VERSION 5.7 ;
  NOWIREEXTENSIONATPIN ON ;
  DIVIDERCHAR "/" ;
  BUSBITCHARS "[]" ;
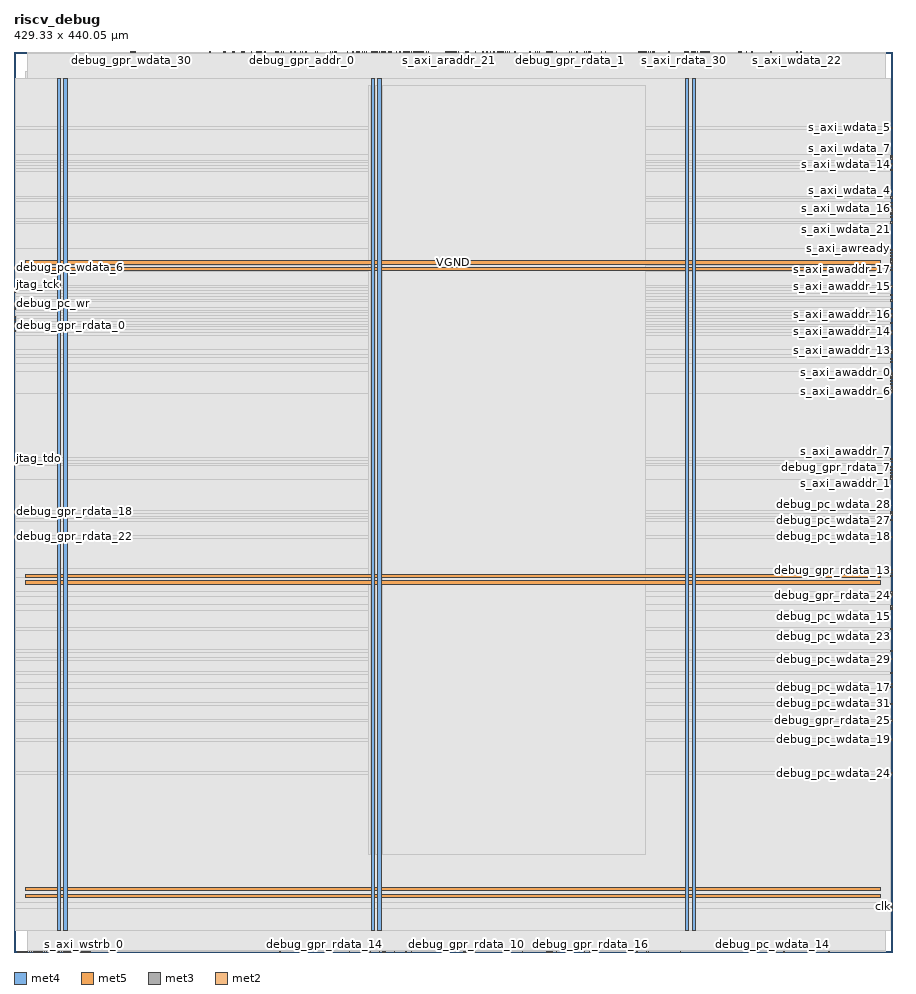
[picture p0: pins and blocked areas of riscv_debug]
MACRO riscv_debug
  CLASS BLOCK ;
  FOREIGN riscv_debug ;
  ORIGIN 0.000 0.000 ;
  SIZE 429.330 BY 440.050 ;
  PIN VGND
    DIRECTION INOUT ;
    USE GROUND ;
    PORT
      LAYER met4 ;
        RECT 24.340 10.640 25.940 427.280 ;
    END
    PORT
      LAYER met4 ;
        RECT 177.940 10.640 179.540 427.280 ;
    END
    PORT
      LAYER met4 ;
        RECT 331.540 10.640 333.140 427.280 ;
    END
    PORT
      LAYER met5 ;
        RECT 5.520 30.030 423.660 31.630 ;
    END
    PORT
      LAYER met5 ;
        RECT 5.520 183.210 423.660 184.810 ;
    END
    PORT
      LAYER met5 ;
        RECT 5.520 336.390 423.660 337.990 ;
    END
  END VGND
  PIN VPWR
    DIRECTION INOUT ;
    USE POWER ;
    PORT
      LAYER met4 ;
        RECT 21.040 10.640 22.640 427.280 ;
    END
    PORT
      LAYER met4 ;
        RECT 174.640 10.640 176.240 427.280 ;
    END
    PORT
      LAYER met4 ;
        RECT 328.240 10.640 329.840 427.280 ;
    END
    PORT
      LAYER met5 ;
        RECT 5.520 26.730 423.660 28.330 ;
    END
    PORT
      LAYER met5 ;
        RECT 5.520 179.910 423.660 181.510 ;
    END
    PORT
      LAYER met5 ;
        RECT 5.520 333.090 423.660 334.690 ;
    END
  END VPWR
  PIN clk
    DIRECTION INPUT ;
    USE SIGNAL ;
    ANTENNAGATEAREA 1.286700 ;
    ANTENNADIFFAREA 0.434700 ;
    PORT
      LAYER met3 ;
        RECT 428.730 21.800 429.330 22.400 ;
    END
  END clk
  PIN debug_gpr_addr_0
    DIRECTION OUTPUT ;
    USE SIGNAL ;
    ANTENNAGATEAREA 0.434700 ;
    ANTENNADIFFAREA 1.137600 ;
    PORT
      LAYER met2 ;
        RECT 140.850 439.770 141.130 440.050 ;
    END
  END debug_gpr_addr_0
  PIN debug_gpr_addr_1
    DIRECTION OUTPUT ;
    USE SIGNAL ;
    ANTENNAGATEAREA 0.434700 ;
    ANTENNADIFFAREA 1.137600 ;
    PORT
      LAYER met2 ;
        RECT 184.090 439.770 184.370 440.050 ;
    END
  END debug_gpr_addr_1
  PIN debug_gpr_addr_2
    DIRECTION OUTPUT ;
    USE SIGNAL ;
    ANTENNAGATEAREA 0.434700 ;
    ANTENNADIFFAREA 1.137600 ;
    PORT
      LAYER met2 ;
        RECT 176.730 439.770 177.010 440.050 ;
    END
  END debug_gpr_addr_2
  PIN debug_gpr_addr_3
    DIRECTION OUTPUT ;
    USE SIGNAL ;
    ANTENNAGATEAREA 0.434700 ;
    ANTENNADIFFAREA 1.137600 ;
    PORT
      LAYER met2 ;
        RECT 181.330 439.770 181.610 440.050 ;
    END
  END debug_gpr_addr_3
  PIN debug_gpr_addr_4
    DIRECTION OUTPUT ;
    USE SIGNAL ;
    ANTENNAGATEAREA 0.434700 ;
    ANTENNADIFFAREA 1.137600 ;
    PORT
      LAYER met2 ;
        RECT 177.650 439.770 177.930 440.050 ;
    END
  END debug_gpr_addr_4
  PIN debug_gpr_rdata_0
    DIRECTION INPUT ;
    USE SIGNAL ;
    ANTENNAGATEAREA 0.647700 ;
    ANTENNADIFFAREA 0.434700 ;
    PORT
      LAYER met3 ;
        RECT 0.000 306.040 0.600 306.640 ;
    END
  END debug_gpr_rdata_0
  PIN debug_gpr_rdata_1
    DIRECTION INPUT ;
    USE SIGNAL ;
    ANTENNAGATEAREA 0.647700 ;
    ANTENNADIFFAREA 0.434700 ;
    PORT
      LAYER met2 ;
        RECT 271.490 439.770 271.770 440.050 ;
    END
  END debug_gpr_rdata_1
  PIN debug_gpr_rdata_10
    DIRECTION INPUT ;
    USE SIGNAL ;
    ANTENNAGATEAREA 0.647700 ;
    ANTENNADIFFAREA 0.434700 ;
    PORT
      LAYER met2 ;
        RECT 220.890 0.000 221.170 0.280 ;
    END
  END debug_gpr_rdata_10
  PIN debug_gpr_rdata_11
    DIRECTION INPUT ;
    USE SIGNAL ;
    ANTENNAGATEAREA 0.647700 ;
    ANTENNADIFFAREA 0.434700 ;
    PORT
      LAYER met2 ;
        RECT 283.450 0.000 283.730 0.280 ;
    END
  END debug_gpr_rdata_11
  PIN debug_gpr_rdata_12
    DIRECTION INPUT ;
    USE SIGNAL ;
    ANTENNAGATEAREA 0.647700 ;
    ANTENNADIFFAREA 0.434700 ;
    PORT
      LAYER met2 ;
        RECT 221.810 0.000 222.090 0.280 ;
    END
  END debug_gpr_rdata_12
  PIN debug_gpr_rdata_13
    DIRECTION INPUT ;
    USE SIGNAL ;
    ANTENNAGATEAREA 0.647700 ;
    ANTENNADIFFAREA 0.434700 ;
    PORT
      LAYER met3 ;
        RECT 428.730 186.360 429.330 186.960 ;
    END
  END debug_gpr_rdata_13
  PIN debug_gpr_rdata_14
    DIRECTION INPUT ;
    USE SIGNAL ;
    ANTENNAGATEAREA 0.647700 ;
    ANTENNADIFFAREA 0.434700 ;
    PORT
      LAYER met2 ;
        RECT 151.890 0.000 152.170 0.280 ;
    END
  END debug_gpr_rdata_14
  PIN debug_gpr_rdata_15
    DIRECTION INPUT ;
    USE SIGNAL ;
    ANTENNAGATEAREA 0.647700 ;
    ANTENNADIFFAREA 0.434700 ;
    PORT
      LAYER met2 ;
        RECT 191.450 0.000 191.730 0.280 ;
    END
  END debug_gpr_rdata_15
  PIN debug_gpr_rdata_16
    DIRECTION INPUT ;
    USE SIGNAL ;
    ANTENNAGATEAREA 0.647700 ;
    ANTENNADIFFAREA 0.434700 ;
    PORT
      LAYER met2 ;
        RECT 281.610 0.000 281.890 0.280 ;
    END
  END debug_gpr_rdata_16
  PIN debug_gpr_rdata_17
    DIRECTION INPUT ;
    USE SIGNAL ;
    ANTENNAGATEAREA 0.647700 ;
    ANTENNADIFFAREA 0.434700 ;
    PORT
      LAYER met2 ;
        RECT 178.570 0.000 178.850 0.280 ;
    END
  END debug_gpr_rdata_17
  PIN debug_gpr_rdata_18
    DIRECTION INPUT ;
    USE SIGNAL ;
    ANTENNAGATEAREA 0.647700 ;
    ANTENNADIFFAREA 0.434700 ;
    PORT
      LAYER met3 ;
        RECT 0.000 214.920 0.600 215.520 ;
    END
  END debug_gpr_rdata_18
  PIN debug_gpr_rdata_19
    DIRECTION INPUT ;
    USE SIGNAL ;
    ANTENNAGATEAREA 0.647700 ;
    ANTENNADIFFAREA 0.434700 ;
    PORT
      LAYER met2 ;
        RECT 219.970 0.000 220.250 0.280 ;
    END
  END debug_gpr_rdata_19
  PIN debug_gpr_rdata_2
    DIRECTION INPUT ;
    USE SIGNAL ;
    ANTENNAGATEAREA 0.647700 ;
    ANTENNADIFFAREA 0.434700 ;
    PORT
      LAYER met3 ;
        RECT 0.000 303.320 0.600 303.920 ;
    END
  END debug_gpr_rdata_2
  PIN debug_gpr_rdata_20
    DIRECTION INPUT ;
    USE SIGNAL ;
    ANTENNAGATEAREA 0.647700 ;
    ANTENNADIFFAREA 0.434700 ;
    PORT
      LAYER met2 ;
        RECT 309.210 0.000 309.490 0.280 ;
    END
  END debug_gpr_rdata_20
  PIN debug_gpr_rdata_21
    DIRECTION INPUT ;
    USE SIGNAL ;
    ANTENNAGATEAREA 0.647700 ;
    ANTENNADIFFAREA 0.434700 ;
    PORT
      LAYER met2 ;
        RECT 260.450 0.000 260.730 0.280 ;
    END
  END debug_gpr_rdata_21
  PIN debug_gpr_rdata_22
    DIRECTION INPUT ;
    USE SIGNAL ;
    ANTENNAGATEAREA 0.647700 ;
    ANTENNADIFFAREA 0.434700 ;
    PORT
      LAYER met3 ;
        RECT 0.000 202.680 0.600 203.280 ;
    END
  END debug_gpr_rdata_22
  PIN debug_gpr_rdata_23
    DIRECTION INPUT ;
    USE SIGNAL ;
    ANTENNAGATEAREA 0.647700 ;
    ANTENNADIFFAREA 0.434700 ;
    PORT
      LAYER met2 ;
        RECT 306.450 439.770 306.730 440.050 ;
    END
  END debug_gpr_rdata_23
  PIN debug_gpr_rdata_24
    DIRECTION INPUT ;
    USE SIGNAL ;
    ANTENNAGATEAREA 0.647700 ;
    ANTENNADIFFAREA 0.434700 ;
    PORT
      LAYER met3 ;
        RECT 428.730 174.120 429.330 174.720 ;
    END
  END debug_gpr_rdata_24
  PIN debug_gpr_rdata_25
    DIRECTION INPUT ;
    USE SIGNAL ;
    ANTENNAGATEAREA 0.647700 ;
    ANTENNADIFFAREA 0.434700 ;
    PORT
      LAYER met3 ;
        RECT 428.730 112.920 429.330 113.520 ;
    END
  END debug_gpr_rdata_25
  PIN debug_gpr_rdata_26
    DIRECTION INPUT ;
    USE SIGNAL ;
    ANTENNAGATEAREA 0.647700 ;
    ANTENNADIFFAREA 0.434700 ;
    PORT
      LAYER met2 ;
        RECT 181.330 0.000 181.610 0.280 ;
    END
  END debug_gpr_rdata_26
  PIN debug_gpr_rdata_27
    DIRECTION INPUT ;
    USE SIGNAL ;
    ANTENNAGATEAREA 0.647700 ;
    ANTENNADIFFAREA 0.434700 ;
    PORT
      LAYER met2 ;
        RECT 129.810 0.000 130.090 0.280 ;
    END
  END debug_gpr_rdata_27
  PIN debug_gpr_rdata_28
    DIRECTION INPUT ;
    USE SIGNAL ;
    ANTENNAGATEAREA 0.647700 ;
    ANTENNADIFFAREA 0.434700 ;
    PORT
      LAYER met2 ;
        RECT 305.530 439.770 305.810 440.050 ;
    END
  END debug_gpr_rdata_28
  PIN debug_gpr_rdata_29
    DIRECTION INPUT ;
    USE SIGNAL ;
    ANTENNAGATEAREA 0.647700 ;
    ANTENNADIFFAREA 0.434700 ;
    PORT
      LAYER met2 ;
        RECT 198.810 439.770 199.090 440.050 ;
    END
  END debug_gpr_rdata_29
  PIN debug_gpr_rdata_3
    DIRECTION INPUT ;
    USE SIGNAL ;
    ANTENNAGATEAREA 0.647700 ;
    ANTENNADIFFAREA 0.434700 ;
    PORT
      LAYER met2 ;
        RECT 225.490 439.770 225.770 440.050 ;
    END
  END debug_gpr_rdata_3
  PIN debug_gpr_rdata_30
    DIRECTION INPUT ;
    USE SIGNAL ;
    ANTENNAGATEAREA 0.647700 ;
    ANTENNADIFFAREA 0.434700 ;
    PORT
      LAYER met2 ;
        RECT 311.970 439.770 312.250 440.050 ;
    END
  END debug_gpr_rdata_30
  PIN debug_gpr_rdata_31
    DIRECTION INPUT ;
    USE SIGNAL ;
    ANTENNAGATEAREA 0.647700 ;
    ANTENNADIFFAREA 0.434700 ;
    PORT
      LAYER met2 ;
        RECT 168.450 439.770 168.730 440.050 ;
    END
  END debug_gpr_rdata_31
  PIN debug_gpr_rdata_4
    DIRECTION INPUT ;
    USE SIGNAL ;
    ANTENNAGATEAREA 0.647700 ;
    ANTENNADIFFAREA 0.434700 ;
    PORT
      LAYER met2 ;
        RECT 169.370 0.000 169.650 0.280 ;
    END
  END debug_gpr_rdata_4
  PIN debug_gpr_rdata_5
    DIRECTION INPUT ;
    USE SIGNAL ;
    ANTENNAGATEAREA 0.647700 ;
    ANTENNADIFFAREA 0.434700 ;
    PORT
      LAYER met2 ;
        RECT 180.410 0.000 180.690 0.280 ;
    END
  END debug_gpr_rdata_5
  PIN debug_gpr_rdata_6
    DIRECTION INPUT ;
    USE SIGNAL ;
    ANTENNAGATEAREA 0.647700 ;
    ANTENNADIFFAREA 0.434700 ;
    PORT
      LAYER met2 ;
        RECT 263.210 0.000 263.490 0.280 ;
    END
  END debug_gpr_rdata_6
  PIN debug_gpr_rdata_7
    DIRECTION INPUT ;
    USE SIGNAL ;
    ANTENNAGATEAREA 0.647700 ;
    ANTENNADIFFAREA 0.434700 ;
    PORT
      LAYER met3 ;
        RECT 428.730 236.680 429.330 237.280 ;
    END
  END debug_gpr_rdata_7
  PIN debug_gpr_rdata_8
    DIRECTION INPUT ;
    USE SIGNAL ;
    ANTENNAGATEAREA 0.647700 ;
    ANTENNADIFFAREA 0.434700 ;
    PORT
      LAYER met2 ;
        RECT 192.370 439.770 192.650 440.050 ;
    END
  END debug_gpr_rdata_8
  PIN debug_gpr_rdata_9
    DIRECTION INPUT ;
    USE SIGNAL ;
    ANTENNAGATEAREA 0.647700 ;
    ANTENNADIFFAREA 0.434700 ;
    PORT
      LAYER met2 ;
        RECT 163.850 0.000 164.130 0.280 ;
    END
  END debug_gpr_rdata_9
  PIN debug_gpr_wdata_0
    DIRECTION OUTPUT ;
    USE SIGNAL ;
    ANTENNAGATEAREA 0.434700 ;
    ANTENNADIFFAREA 1.137600 ;
    PORT
      LAYER met2 ;
        RECT 147.290 439.770 147.570 440.050 ;
    END
  END debug_gpr_wdata_0
  PIN debug_gpr_wdata_1
    DIRECTION OUTPUT ;
    USE SIGNAL ;
    ANTENNAGATEAREA 0.434700 ;
    ANTENNADIFFAREA 1.137600 ;
    PORT
      LAYER met2 ;
        RECT 112.330 439.770 112.610 440.050 ;
    END
  END debug_gpr_wdata_1
  PIN debug_gpr_wdata_10
    DIRECTION OUTPUT ;
    USE SIGNAL ;
    ANTENNAGATEAREA 0.434700 ;
    ANTENNADIFFAREA 1.137600 ;
    PORT
      LAYER met2 ;
        RECT 102.210 439.770 102.490 440.050 ;
    END
  END debug_gpr_wdata_10
  PIN debug_gpr_wdata_11
    DIRECTION OUTPUT ;
    USE SIGNAL ;
    ANTENNAGATEAREA 0.434700 ;
    ANTENNADIFFAREA 1.137600 ;
    PORT
      LAYER met2 ;
        RECT 195.130 439.770 195.410 440.050 ;
    END
  END debug_gpr_wdata_11
  PIN debug_gpr_wdata_12
    DIRECTION OUTPUT ;
    USE SIGNAL ;
    ANTENNAGATEAREA 0.434700 ;
    ANTENNADIFFAREA 1.137600 ;
    PORT
      LAYER met2 ;
        RECT 139.930 439.770 140.210 440.050 ;
    END
  END debug_gpr_wdata_12
  PIN debug_gpr_wdata_13
    DIRECTION OUTPUT ;
    USE SIGNAL ;
    ANTENNAGATEAREA 0.434700 ;
    ANTENNADIFFAREA 1.137600 ;
    PORT
      LAYER met2 ;
        RECT 128.890 439.770 129.170 440.050 ;
    END
  END debug_gpr_wdata_13
  PIN debug_gpr_wdata_14
    DIRECTION OUTPUT ;
    USE SIGNAL ;
    ANTENNAGATEAREA 0.434700 ;
    ANTENNADIFFAREA 1.137600 ;
    PORT
      LAYER met2 ;
        RECT 180.410 439.770 180.690 440.050 ;
    END
  END debug_gpr_wdata_14
  PIN debug_gpr_wdata_15
    DIRECTION OUTPUT ;
    USE SIGNAL ;
    ANTENNAGATEAREA 0.434700 ;
    ANTENNADIFFAREA 1.137600 ;
    PORT
      LAYER met2 ;
        RECT 119.690 439.770 119.970 440.050 ;
    END
  END debug_gpr_wdata_15
  PIN debug_gpr_wdata_16
    DIRECTION OUTPUT ;
    USE SIGNAL ;
    ANTENNAGATEAREA 0.434700 ;
    ANTENNADIFFAREA 1.137600 ;
    PORT
      LAYER met2 ;
        RECT 137.170 439.770 137.450 440.050 ;
    END
  END debug_gpr_wdata_16
  PIN debug_gpr_wdata_17
    DIRECTION OUTPUT ;
    USE SIGNAL ;
    ANTENNAGATEAREA 0.434700 ;
    ANTENNADIFFAREA 1.137600 ;
    PORT
      LAYER met2 ;
        RECT 156.490 439.770 156.770 440.050 ;
    END
  END debug_gpr_wdata_17
  PIN debug_gpr_wdata_18
    DIRECTION OUTPUT ;
    USE SIGNAL ;
    ANTENNAGATEAREA 0.434700 ;
    ANTENNADIFFAREA 1.137600 ;
    PORT
      LAYER met2 ;
        RECT 196.970 439.770 197.250 440.050 ;
    END
  END debug_gpr_wdata_18
  PIN debug_gpr_wdata_19
    DIRECTION OUTPUT ;
    USE SIGNAL ;
    ANTENNAGATEAREA 0.434700 ;
    ANTENNADIFFAREA 1.137600 ;
    PORT
      LAYER met2 ;
        RECT 118.770 439.770 119.050 440.050 ;
    END
  END debug_gpr_wdata_19
  PIN debug_gpr_wdata_2
    DIRECTION OUTPUT ;
    USE SIGNAL ;
    ANTENNAGATEAREA 0.434700 ;
    ANTENNADIFFAREA 1.137600 ;
    PORT
      LAYER met2 ;
        RECT 170.290 439.770 170.570 440.050 ;
    END
  END debug_gpr_wdata_2
  PIN debug_gpr_wdata_20
    DIRECTION OUTPUT ;
    USE SIGNAL ;
    ANTENNAGATEAREA 0.434700 ;
    ANTENNADIFFAREA 1.137600 ;
    PORT
      LAYER met2 ;
        RECT 194.210 439.770 194.490 440.050 ;
    END
  END debug_gpr_wdata_20
  PIN debug_gpr_wdata_21
    DIRECTION OUTPUT ;
    USE SIGNAL ;
    ANTENNAGATEAREA 0.434700 ;
    ANTENNADIFFAREA 1.137600 ;
    PORT
      LAYER met2 ;
        RECT 122.450 439.770 122.730 440.050 ;
    END
  END debug_gpr_wdata_21
  PIN debug_gpr_wdata_22
    DIRECTION OUTPUT ;
    USE SIGNAL ;
    ANTENNAGATEAREA 0.434700 ;
    ANTENNADIFFAREA 1.137600 ;
    PORT
      LAYER met2 ;
        RECT 193.290 439.770 193.570 440.050 ;
    END
  END debug_gpr_wdata_22
  PIN debug_gpr_wdata_23
    DIRECTION OUTPUT ;
    USE SIGNAL ;
    ANTENNAGATEAREA 0.434700 ;
    ANTENNADIFFAREA 1.137600 ;
    PORT
      LAYER met2 ;
        RECT 142.690 439.770 142.970 440.050 ;
    END
  END debug_gpr_wdata_23
  PIN debug_gpr_wdata_24
    DIRECTION OUTPUT ;
    USE SIGNAL ;
    ANTENNAGATEAREA 0.434700 ;
    ANTENNADIFFAREA 1.137600 ;
    PORT
      LAYER met2 ;
        RECT 135.330 439.770 135.610 440.050 ;
    END
  END debug_gpr_wdata_24
  PIN debug_gpr_wdata_25
    DIRECTION OUTPUT ;
    USE SIGNAL ;
    ANTENNAGATEAREA 0.434700 ;
    ANTENNADIFFAREA 1.137600 ;
    PORT
      LAYER met2 ;
        RECT 111.410 439.770 111.690 440.050 ;
    END
  END debug_gpr_wdata_25
  PIN debug_gpr_wdata_26
    DIRECTION OUTPUT ;
    USE SIGNAL ;
    ANTENNAGATEAREA 0.434700 ;
    ANTENNADIFFAREA 1.137600 ;
    PORT
      LAYER met2 ;
        RECT 131.650 439.770 131.930 440.050 ;
    END
  END debug_gpr_wdata_26
  PIN debug_gpr_wdata_27
    DIRECTION OUTPUT ;
    USE SIGNAL ;
    ANTENNAGATEAREA 0.434700 ;
    ANTENNADIFFAREA 1.137600 ;
    PORT
      LAYER met2 ;
        RECT 157.410 439.770 157.690 440.050 ;
    END
  END debug_gpr_wdata_27
  PIN debug_gpr_wdata_28
    DIRECTION OUTPUT ;
    USE SIGNAL ;
    ANTENNAGATEAREA 0.434700 ;
    ANTENNADIFFAREA 1.137600 ;
    PORT
      LAYER met2 ;
        RECT 165.690 439.770 165.970 440.050 ;
    END
  END debug_gpr_wdata_28
  PIN debug_gpr_wdata_29
    DIRECTION OUTPUT ;
    USE SIGNAL ;
    ANTENNAGATEAREA 0.434700 ;
    ANTENNADIFFAREA 1.137600 ;
    PORT
      LAYER met2 ;
        RECT 95.770 439.770 96.050 440.050 ;
    END
  END debug_gpr_wdata_29
  PIN debug_gpr_wdata_3
    DIRECTION OUTPUT ;
    USE SIGNAL ;
    ANTENNAGATEAREA 0.434700 ;
    ANTENNADIFFAREA 1.137600 ;
    PORT
      LAYER met2 ;
        RECT 171.210 439.770 171.490 440.050 ;
    END
  END debug_gpr_wdata_3
  PIN debug_gpr_wdata_30
    DIRECTION OUTPUT ;
    USE SIGNAL ;
    ANTENNAGATEAREA 0.434700 ;
    ANTENNADIFFAREA 1.137600 ;
    PORT
      LAYER met2 ;
        RECT 57.130 439.770 57.410 440.050 ;
    END
  END debug_gpr_wdata_30
  PIN debug_gpr_wdata_31
    DIRECTION OUTPUT ;
    USE SIGNAL ;
    ANTENNAGATEAREA 0.434700 ;
    ANTENNADIFFAREA 1.137600 ;
    PORT
      LAYER met2 ;
        RECT 120.610 439.770 120.890 440.050 ;
    END
  END debug_gpr_wdata_31
  PIN debug_gpr_wdata_4
    DIRECTION OUTPUT ;
    USE SIGNAL ;
    ANTENNAGATEAREA 0.434700 ;
    ANTENNADIFFAREA 1.137600 ;
    PORT
      LAYER met2 ;
        RECT 162.930 439.770 163.210 440.050 ;
    END
  END debug_gpr_wdata_4
  PIN debug_gpr_wdata_5
    DIRECTION OUTPUT ;
    USE SIGNAL ;
    ANTENNAGATEAREA 0.434700 ;
    ANTENNADIFFAREA 1.137600 ;
    PORT
      LAYER met2 ;
        RECT 190.530 439.770 190.810 440.050 ;
    END
  END debug_gpr_wdata_5
  PIN debug_gpr_wdata_6
    DIRECTION OUTPUT ;
    USE SIGNAL ;
    ANTENNAGATEAREA 0.434700 ;
    ANTENNADIFFAREA 1.137600 ;
    PORT
      LAYER met2 ;
        RECT 155.570 439.770 155.850 440.050 ;
    END
  END debug_gpr_wdata_6
  PIN debug_gpr_wdata_7
    DIRECTION OUTPUT ;
    USE SIGNAL ;
    ANTENNAGATEAREA 0.434700 ;
    ANTENNADIFFAREA 1.137600 ;
    PORT
      LAYER met2 ;
        RECT 199.730 439.770 200.010 440.050 ;
    END
  END debug_gpr_wdata_7
  PIN debug_gpr_wdata_8
    DIRECTION OUTPUT ;
    USE SIGNAL ;
    ANTENNAGATEAREA 0.434700 ;
    ANTENNADIFFAREA 1.137600 ;
    PORT
      LAYER met2 ;
        RECT 106.810 439.770 107.090 440.050 ;
    END
  END debug_gpr_wdata_8
  PIN debug_gpr_wdata_9
    DIRECTION OUTPUT ;
    USE SIGNAL ;
    ANTENNAGATEAREA 0.434700 ;
    ANTENNADIFFAREA 1.137600 ;
    PORT
      LAYER met2 ;
        RECT 167.530 439.770 167.810 440.050 ;
    END
  END debug_gpr_wdata_9
  PIN debug_gpr_wr
    DIRECTION OUTPUT ;
    USE SIGNAL ;
    ANTENNAGATEAREA 0.434700 ;
    ANTENNADIFFAREA 1.137600 ;
    PORT
      LAYER met3 ;
        RECT 0.000 315.560 0.600 316.160 ;
    END
  END debug_gpr_wr
  PIN debug_halt
    DIRECTION OUTPUT ;
    USE SIGNAL ;
    ANTENNAGATEAREA 0.434700 ;
    ANTENNADIFFAREA 1.137600 ;
    PORT
      LAYER met2 ;
        RECT 186.850 439.770 187.130 440.050 ;
    END
  END debug_halt
  PIN debug_halted
    DIRECTION INPUT ;
    USE SIGNAL ;
    ANTENNAGATEAREA 0.647700 ;
    ANTENNADIFFAREA 0.434700 ;
    PORT
      LAYER met2 ;
        RECT 220.890 439.770 221.170 440.050 ;
    END
  END debug_halted
  PIN debug_pc_0
    DIRECTION INPUT ;
    USE SIGNAL ;
    PORT
      LAYER met2 ;
        RECT 1.930 0.000 2.210 0.280 ;
    END
  END debug_pc_0
  PIN debug_pc_1
    DIRECTION INPUT ;
    USE SIGNAL ;
    PORT
      LAYER met2 ;
        RECT 2.850 0.000 3.130 0.280 ;
    END
  END debug_pc_1
  PIN debug_pc_10
    DIRECTION INPUT ;
    USE SIGNAL ;
    PORT
      LAYER met2 ;
        RECT 3.770 0.000 4.050 0.280 ;
    END
  END debug_pc_10
  PIN debug_pc_11
    DIRECTION INPUT ;
    USE SIGNAL ;
    PORT
      LAYER met2 ;
        RECT 4.690 0.000 4.970 0.280 ;
    END
  END debug_pc_11
  PIN debug_pc_12
    DIRECTION INPUT ;
    USE SIGNAL ;
    PORT
      LAYER met2 ;
        RECT 5.610 0.000 5.890 0.280 ;
    END
  END debug_pc_12
  PIN debug_pc_13
    DIRECTION INPUT ;
    USE SIGNAL ;
    PORT
      LAYER met2 ;
        RECT 6.530 0.000 6.810 0.280 ;
    END
  END debug_pc_13
  PIN debug_pc_14
    DIRECTION INPUT ;
    USE SIGNAL ;
    PORT
      LAYER met2 ;
        RECT 7.450 0.000 7.730 0.280 ;
    END
  END debug_pc_14
  PIN debug_pc_15
    DIRECTION INPUT ;
    USE SIGNAL ;
    PORT
      LAYER met2 ;
        RECT 8.370 0.000 8.650 0.280 ;
    END
  END debug_pc_15
  PIN debug_pc_16
    DIRECTION INPUT ;
    USE SIGNAL ;
    PORT
      LAYER met2 ;
        RECT 9.290 0.000 9.570 0.280 ;
    END
  END debug_pc_16
  PIN debug_pc_17
    DIRECTION INPUT ;
    USE SIGNAL ;
    PORT
      LAYER met2 ;
        RECT 10.210 0.000 10.490 0.280 ;
    END
  END debug_pc_17
  PIN debug_pc_18
    DIRECTION INPUT ;
    USE SIGNAL ;
    PORT
      LAYER met2 ;
        RECT 11.130 0.000 11.410 0.280 ;
    END
  END debug_pc_18
  PIN debug_pc_19
    DIRECTION INPUT ;
    USE SIGNAL ;
    PORT
      LAYER met2 ;
        RECT 12.050 0.000 12.330 0.280 ;
    END
  END debug_pc_19
  PIN debug_pc_2
    DIRECTION INPUT ;
    USE SIGNAL ;
    PORT
      LAYER met2 ;
        RECT 12.970 0.000 13.250 0.280 ;
    END
  END debug_pc_2
  PIN debug_pc_20
    DIRECTION INPUT ;
    USE SIGNAL ;
    PORT
      LAYER met2 ;
        RECT 13.890 0.000 14.170 0.280 ;
    END
  END debug_pc_20
  PIN debug_pc_21
    DIRECTION INPUT ;
    USE SIGNAL ;
    PORT
      LAYER met2 ;
        RECT 14.810 0.000 15.090 0.280 ;
    END
  END debug_pc_21
  PIN debug_pc_22
    DIRECTION INPUT ;
    USE SIGNAL ;
    PORT
      LAYER met2 ;
        RECT 15.730 0.000 16.010 0.280 ;
    END
  END debug_pc_22
  PIN debug_pc_23
    DIRECTION INPUT ;
    USE SIGNAL ;
    PORT
      LAYER met2 ;
        RECT 16.650 0.000 16.930 0.280 ;
    END
  END debug_pc_23
  PIN debug_pc_24
    DIRECTION INPUT ;
    USE SIGNAL ;
    PORT
      LAYER met2 ;
        RECT 17.570 0.000 17.850 0.280 ;
    END
  END debug_pc_24
  PIN debug_pc_25
    DIRECTION INPUT ;
    USE SIGNAL ;
    PORT
      LAYER met2 ;
        RECT 18.490 0.000 18.770 0.280 ;
    END
  END debug_pc_25
  PIN debug_pc_26
    DIRECTION INPUT ;
    USE SIGNAL ;
    PORT
      LAYER met2 ;
        RECT 19.410 0.000 19.690 0.280 ;
    END
  END debug_pc_26
  PIN debug_pc_27
    DIRECTION INPUT ;
    USE SIGNAL ;
    PORT
      LAYER met2 ;
        RECT 20.330 0.000 20.610 0.280 ;
    END
  END debug_pc_27
  PIN debug_pc_28
    DIRECTION INPUT ;
    USE SIGNAL ;
    PORT
      LAYER met2 ;
        RECT 21.250 0.000 21.530 0.280 ;
    END
  END debug_pc_28
  PIN debug_pc_29
    DIRECTION INPUT ;
    USE SIGNAL ;
    PORT
      LAYER met2 ;
        RECT 22.170 0.000 22.450 0.280 ;
    END
  END debug_pc_29
  PIN debug_pc_3
    DIRECTION INPUT ;
    USE SIGNAL ;
    PORT
      LAYER met2 ;
        RECT 23.090 0.000 23.370 0.280 ;
    END
  END debug_pc_3
  PIN debug_pc_30
    DIRECTION INPUT ;
    USE SIGNAL ;
    PORT
      LAYER met2 ;
        RECT 24.010 0.000 24.290 0.280 ;
    END
  END debug_pc_30
  PIN debug_pc_31
    DIRECTION INPUT ;
    USE SIGNAL ;
    PORT
      LAYER met2 ;
        RECT 24.930 0.000 25.210 0.280 ;
    END
  END debug_pc_31
  PIN debug_pc_4
    DIRECTION INPUT ;
    USE SIGNAL ;
    PORT
      LAYER met2 ;
        RECT 25.850 0.000 26.130 0.280 ;
    END
  END debug_pc_4
  PIN debug_pc_5
    DIRECTION INPUT ;
    USE SIGNAL ;
    PORT
      LAYER met2 ;
        RECT 26.770 0.000 27.050 0.280 ;
    END
  END debug_pc_5
  PIN debug_pc_6
    DIRECTION INPUT ;
    USE SIGNAL ;
    PORT
      LAYER met2 ;
        RECT 27.690 0.000 27.970 0.280 ;
    END
  END debug_pc_6
  PIN debug_pc_7
    DIRECTION INPUT ;
    USE SIGNAL ;
    PORT
      LAYER met2 ;
        RECT 28.610 0.000 28.890 0.280 ;
    END
  END debug_pc_7
  PIN debug_pc_8
    DIRECTION INPUT ;
    USE SIGNAL ;
    PORT
      LAYER met2 ;
        RECT 29.530 0.000 29.810 0.280 ;
    END
  END debug_pc_8
  PIN debug_pc_9
    DIRECTION INPUT ;
    USE SIGNAL ;
    PORT
      LAYER met2 ;
        RECT 30.450 0.000 30.730 0.280 ;
    END
  END debug_pc_9
  PIN debug_pc_wdata_0
    DIRECTION OUTPUT ;
    USE SIGNAL ;
    ANTENNAGATEAREA 0.434700 ;
    ANTENNADIFFAREA 1.137600 ;
    PORT
      LAYER met2 ;
        RECT 58.050 439.770 58.330 440.050 ;
    END
  END debug_pc_wdata_0
  PIN debug_pc_wdata_1
    DIRECTION OUTPUT ;
    USE SIGNAL ;
    ANTENNAGATEAREA 0.434700 ;
    ANTENNADIFFAREA 1.137600 ;
    PORT
      LAYER met2 ;
        RECT 196.050 439.770 196.330 440.050 ;
    END
  END debug_pc_wdata_1
  PIN debug_pc_wdata_10
    DIRECTION OUTPUT ;
    USE SIGNAL ;
    ANTENNAGATEAREA 0.434700 ;
    ANTENNADIFFAREA 1.137600 ;
    PORT
      LAYER met2 ;
        RECT 107.730 439.770 108.010 440.050 ;
    END
  END debug_pc_wdata_10
  PIN debug_pc_wdata_11
    DIRECTION OUTPUT ;
    USE SIGNAL ;
    ANTENNAGATEAREA 0.434700 ;
    ANTENNADIFFAREA 1.137600 ;
    PORT
      LAYER met2 ;
        RECT 148.210 439.770 148.490 440.050 ;
    END
  END debug_pc_wdata_11
  PIN debug_pc_wdata_12
    DIRECTION OUTPUT ;
    USE SIGNAL ;
    ANTENNAGATEAREA 0.434700 ;
    ANTENNADIFFAREA 1.137600 ;
    PORT
      LAYER met2 ;
        RECT 191.450 439.770 191.730 440.050 ;
    END
  END debug_pc_wdata_12
  PIN debug_pc_wdata_13
    DIRECTION OUTPUT ;
    USE SIGNAL ;
    ANTENNAGATEAREA 0.434700 ;
    ANTENNADIFFAREA 1.137600 ;
    PORT
      LAYER met2 ;
        RECT 197.890 439.770 198.170 440.050 ;
    END
  END debug_pc_wdata_13
  PIN debug_pc_wdata_14
    DIRECTION OUTPUT ;
    USE SIGNAL ;
    ANTENNAGATEAREA 0.434700 ;
    ANTENNADIFFAREA 1.137600 ;
    PORT
      LAYER met2 ;
        RECT 370.850 0.000 371.130 0.280 ;
    END
  END debug_pc_wdata_14
  PIN debug_pc_wdata_15
    DIRECTION OUTPUT ;
    USE SIGNAL ;
    ANTENNAGATEAREA 0.434700 ;
    ANTENNADIFFAREA 1.137600 ;
    PORT
      LAYER met3 ;
        RECT 428.730 167.320 429.330 167.920 ;
    END
  END debug_pc_wdata_15
  PIN debug_pc_wdata_16
    DIRECTION OUTPUT ;
    USE SIGNAL ;
    ANTENNAGATEAREA 0.434700 ;
    ANTENNADIFFAREA 1.137600 ;
    PORT
      LAYER met3 ;
        RECT 428.730 183.640 429.330 184.240 ;
    END
  END debug_pc_wdata_16
  PIN debug_pc_wdata_17
    DIRECTION OUTPUT ;
    USE SIGNAL ;
    ANTENNAGATEAREA 0.434700 ;
    ANTENNADIFFAREA 1.137600 ;
    PORT
      LAYER met3 ;
        RECT 428.730 129.240 429.330 129.840 ;
    END
  END debug_pc_wdata_17
  PIN debug_pc_wdata_18
    DIRECTION OUTPUT ;
    USE SIGNAL ;
    ANTENNAGATEAREA 0.434700 ;
    ANTENNADIFFAREA 1.137600 ;
    PORT
      LAYER met3 ;
        RECT 428.730 202.680 429.330 203.280 ;
    END
  END debug_pc_wdata_18
  PIN debug_pc_wdata_19
    DIRECTION OUTPUT ;
    USE SIGNAL ;
    ANTENNAGATEAREA 0.434700 ;
    ANTENNADIFFAREA 1.137600 ;
    PORT
      LAYER met3 ;
        RECT 428.730 103.400 429.330 104.000 ;
    END
  END debug_pc_wdata_19
  PIN debug_pc_wdata_2
    DIRECTION OUTPUT ;
    USE SIGNAL ;
    ANTENNAGATEAREA 0.434700 ;
    ANTENNADIFFAREA 1.137600 ;
    PORT
      LAYER met2 ;
        RECT 154.650 439.770 154.930 440.050 ;
    END
  END debug_pc_wdata_2
  PIN debug_pc_wdata_20
    DIRECTION OUTPUT ;
    USE SIGNAL ;
    ANTENNAGATEAREA 0.434700 ;
    ANTENNADIFFAREA 1.137600 ;
    PORT
      LAYER met3 ;
        RECT 428.730 146.920 429.330 147.520 ;
    END
  END debug_pc_wdata_20
  PIN debug_pc_wdata_21
    DIRECTION OUTPUT ;
    USE SIGNAL ;
    ANTENNAGATEAREA 0.434700 ;
    ANTENNADIFFAREA 1.137600 ;
    PORT
      LAYER met2 ;
        RECT 376.370 0.000 376.650 0.280 ;
    END
  END debug_pc_wdata_21
  PIN debug_pc_wdata_22
    DIRECTION OUTPUT ;
    USE SIGNAL ;
    ANTENNAGATEAREA 0.434700 ;
    ANTENNADIFFAREA 1.137600 ;
    PORT
      LAYER met2 ;
        RECT 369.930 0.000 370.210 0.280 ;
    END
  END debug_pc_wdata_22
  PIN debug_pc_wdata_23
    DIRECTION OUTPUT ;
    USE SIGNAL ;
    ANTENNAGATEAREA 0.434700 ;
    ANTENNADIFFAREA 1.137600 ;
    PORT
      LAYER met3 ;
        RECT 428.730 157.800 429.330 158.400 ;
    END
  END debug_pc_wdata_23
  PIN debug_pc_wdata_24
    DIRECTION OUTPUT ;
    USE SIGNAL ;
    ANTENNAGATEAREA 0.434700 ;
    ANTENNADIFFAREA 1.137600 ;
    PORT
      LAYER met3 ;
        RECT 428.730 87.080 429.330 87.680 ;
    END
  END debug_pc_wdata_24
  PIN debug_pc_wdata_25
    DIRECTION OUTPUT ;
    USE SIGNAL ;
    ANTENNAGATEAREA 0.434700 ;
    ANTENNADIFFAREA 1.137600 ;
    PORT
      LAYER met2 ;
        RECT 398.450 0.000 398.730 0.280 ;
    END
  END debug_pc_wdata_25
  PIN debug_pc_wdata_26
    DIRECTION OUTPUT ;
    USE SIGNAL ;
    ANTENNAGATEAREA 0.434700 ;
    ANTENNADIFFAREA 1.137600 ;
    PORT
      LAYER met2 ;
        RECT 372.690 0.000 372.970 0.280 ;
    END
  END debug_pc_wdata_26
  PIN debug_pc_wdata_27
    DIRECTION OUTPUT ;
    USE SIGNAL ;
    ANTENNAGATEAREA 0.434700 ;
    ANTENNADIFFAREA 1.137600 ;
    PORT
      LAYER met3 ;
        RECT 428.730 210.840 429.330 211.440 ;
    END
  END debug_pc_wdata_27
  PIN debug_pc_wdata_28
    DIRECTION OUTPUT ;
    USE SIGNAL ;
    ANTENNAGATEAREA 0.434700 ;
    ANTENNADIFFAREA 1.137600 ;
    PORT
      LAYER met3 ;
        RECT 428.730 214.920 429.330 215.520 ;
    END
  END debug_pc_wdata_28
  PIN debug_pc_wdata_29
    DIRECTION OUTPUT ;
    USE SIGNAL ;
    ANTENNAGATEAREA 0.434700 ;
    ANTENNADIFFAREA 1.137600 ;
    PORT
      LAYER met3 ;
        RECT 428.730 142.840 429.330 143.440 ;
    END
  END debug_pc_wdata_29
  PIN debug_pc_wdata_3
    DIRECTION OUTPUT ;
    USE SIGNAL ;
    ANTENNAGATEAREA 0.434700 ;
    ANTENNADIFFAREA 1.137600 ;
    PORT
      LAYER met2 ;
        RECT 103.130 439.770 103.410 440.050 ;
    END
  END debug_pc_wdata_3
  PIN debug_pc_wdata_30
    DIRECTION OUTPUT ;
    USE SIGNAL ;
    ANTENNAGATEAREA 0.434700 ;
    ANTENNADIFFAREA 1.137600 ;
    PORT
      LAYER met3 ;
        RECT 428.730 185.000 429.330 185.600 ;
    END
  END debug_pc_wdata_30
  PIN debug_pc_wdata_31
    DIRECTION OUTPUT ;
    USE SIGNAL ;
    ANTENNAGATEAREA 0.434700 ;
    ANTENNADIFFAREA 1.137600 ;
    PORT
      LAYER met3 ;
        RECT 428.730 121.080 429.330 121.680 ;
    END
  END debug_pc_wdata_31
  PIN debug_pc_wdata_4
    DIRECTION OUTPUT ;
    USE SIGNAL ;
    ANTENNAGATEAREA 0.434700 ;
    ANTENNADIFFAREA 1.137600 ;
    PORT
      LAYER met2 ;
        RECT 183.170 439.770 183.450 440.050 ;
    END
  END debug_pc_wdata_4
  PIN debug_pc_wdata_5
    DIRECTION OUTPUT ;
    USE SIGNAL ;
    ANTENNAGATEAREA 0.434700 ;
    ANTENNADIFFAREA 1.137600 ;
    PORT
      LAYER met2 ;
        RECT 116.010 439.770 116.290 440.050 ;
    END
  END debug_pc_wdata_5
  PIN debug_pc_wdata_6
    DIRECTION OUTPUT ;
    USE SIGNAL ;
    ANTENNAGATEAREA 0.434700 ;
    ANTENNADIFFAREA 1.137600 ;
    PORT
      LAYER met3 ;
        RECT 0.000 334.600 0.600 335.200 ;
    END
  END debug_pc_wdata_6
  PIN debug_pc_wdata_7
    DIRECTION OUTPUT ;
    USE SIGNAL ;
    ANTENNAGATEAREA 0.434700 ;
    ANTENNADIFFAREA 1.137600 ;
    PORT
      LAYER met2 ;
        RECT 127.970 439.770 128.250 440.050 ;
    END
  END debug_pc_wdata_7
  PIN debug_pc_wdata_8
    DIRECTION OUTPUT ;
    USE SIGNAL ;
    ANTENNAGATEAREA 0.434700 ;
    ANTENNADIFFAREA 1.137600 ;
    PORT
      LAYER met2 ;
        RECT 58.970 439.770 59.250 440.050 ;
    END
  END debug_pc_wdata_8
  PIN debug_pc_wdata_9
    DIRECTION OUTPUT ;
    USE SIGNAL ;
    ANTENNAGATEAREA 0.434700 ;
    ANTENNADIFFAREA 1.137600 ;
    PORT
      LAYER met2 ;
        RECT 130.730 439.770 131.010 440.050 ;
    END
  END debug_pc_wdata_9
  PIN debug_pc_wr
    DIRECTION OUTPUT ;
    USE SIGNAL ;
    ANTENNAGATEAREA 0.434700 ;
    ANTENNADIFFAREA 1.137600 ;
    PORT
      LAYER met3 ;
        RECT 0.000 316.920 0.600 317.520 ;
    END
  END debug_pc_wr
  PIN debug_req
    DIRECTION OUTPUT ;
    USE SIGNAL ;
    ANTENNAGATEAREA 0.434700 ;
    ANTENNADIFFAREA 1.137600 ;
    PORT
      LAYER met2 ;
        RECT 174.890 439.770 175.170 440.050 ;
    END
  END debug_req
  PIN debug_resume
    DIRECTION OUTPUT ;
    USE SIGNAL ;
    ANTENNAGATEAREA 0.434700 ;
    ANTENNADIFFAREA 1.137600 ;
    PORT
      LAYER met2 ;
        RECT 248.490 0.000 248.770 0.280 ;
    END
  END debug_resume
  PIN debug_running
    DIRECTION INPUT ;
    USE SIGNAL ;
    ANTENNAGATEAREA 0.647700 ;
    ANTENNADIFFAREA 0.434700 ;
    PORT
      LAYER met2 ;
        RECT 178.570 439.770 178.850 440.050 ;
    END
  END debug_running
  PIN jtag_tck
    DIRECTION INPUT ;
    USE SIGNAL ;
    ANTENNAGATEAREA 0.647700 ;
    ANTENNADIFFAREA 0.434700 ;
    PORT
      LAYER met3 ;
        RECT 0.000 322.360 0.600 322.960 ;
    END
  END jtag_tck
  PIN jtag_tdi
    DIRECTION INPUT ;
    USE SIGNAL ;
    PORT
      LAYER met2 ;
        RECT 31.370 0.000 31.650 0.280 ;
    END
  END jtag_tdi
  PIN jtag_tdo
    DIRECTION OUTPUT ;
    USE SIGNAL ;
    ANTENNAGATEAREA 0.434700 ;
    ANTENNADIFFAREA 1.137600 ;
    PORT
      LAYER met3 ;
        RECT 0.000 240.760 0.600 241.360 ;
    END
  END jtag_tdo
  PIN jtag_tms
    DIRECTION INPUT ;
    USE SIGNAL ;
    PORT
      LAYER met2 ;
        RECT 32.290 0.000 32.570 0.280 ;
    END
  END jtag_tms
  PIN jtag_trst_n
    DIRECTION INPUT ;
    USE SIGNAL ;
    PORT
      LAYER met2 ;
        RECT 33.210 0.000 33.490 0.280 ;
    END
  END jtag_trst_n
  PIN rst_n
    DIRECTION INPUT ;
    USE SIGNAL ;
    ANTENNAGATEAREA 0.647700 ;
    ANTENNADIFFAREA 0.434700 ;
    PORT
      LAYER met3 ;
        RECT 428.730 23.160 429.330 23.760 ;
    END
  END rst_n
  PIN s_axi_araddr_0
    DIRECTION INPUT ;
    USE SIGNAL ;
    ANTENNAGATEAREA 0.647700 ;
    ANTENNADIFFAREA 0.434700 ;
    PORT
      LAYER met2 ;
        RECT 255.850 439.770 256.130 440.050 ;
    END
  END s_axi_araddr_0
  PIN s_axi_araddr_1
    DIRECTION INPUT ;
    USE SIGNAL ;
    ANTENNAGATEAREA 0.647700 ;
    ANTENNADIFFAREA 0.434700 ;
    PORT
      LAYER met2 ;
        RECT 263.210 439.770 263.490 440.050 ;
    END
  END s_axi_araddr_1
  PIN s_axi_araddr_10
    DIRECTION INPUT ;
    USE SIGNAL ;
    ANTENNAGATEAREA 0.647700 ;
    ANTENNADIFFAREA 0.434700 ;
    PORT
      LAYER met2 ;
        RECT 279.770 439.770 280.050 440.050 ;
    END
  END s_axi_araddr_10
  PIN s_axi_araddr_11
    DIRECTION INPUT ;
    USE SIGNAL ;
    ANTENNAGATEAREA 0.647700 ;
    ANTENNADIFFAREA 0.434700 ;
    PORT
      LAYER met2 ;
        RECT 254.930 439.770 255.210 440.050 ;
    END
  END s_axi_araddr_11
  PIN s_axi_araddr_12
    DIRECTION INPUT ;
    USE SIGNAL ;
    ANTENNAGATEAREA 0.647700 ;
    ANTENNADIFFAREA 0.434700 ;
    PORT
      LAYER met2 ;
        RECT 229.170 439.770 229.450 440.050 ;
    END
  END s_axi_araddr_12
  PIN s_axi_araddr_13
    DIRECTION INPUT ;
    USE SIGNAL ;
    ANTENNAGATEAREA 0.647700 ;
    ANTENNADIFFAREA 0.434700 ;
    PORT
      LAYER met2 ;
        RECT 239.290 439.770 239.570 440.050 ;
    END
  END s_axi_araddr_13
  PIN s_axi_araddr_14
    DIRECTION INPUT ;
    USE SIGNAL ;
    ANTENNAGATEAREA 0.647700 ;
    ANTENNADIFFAREA 0.434700 ;
    PORT
      LAYER met2 ;
        RECT 221.810 439.770 222.090 440.050 ;
    END
  END s_axi_araddr_14
  PIN s_axi_araddr_15
    DIRECTION INPUT ;
    USE SIGNAL ;
    ANTENNAGATEAREA 0.647700 ;
    ANTENNADIFFAREA 0.434700 ;
    PORT
      LAYER met2 ;
        RECT 234.690 439.770 234.970 440.050 ;
    END
  END s_axi_araddr_15
  PIN s_axi_araddr_16
    DIRECTION INPUT ;
    USE SIGNAL ;
    ANTENNAGATEAREA 0.647700 ;
    ANTENNADIFFAREA 0.434700 ;
    PORT
      LAYER met2 ;
        RECT 215.370 439.770 215.650 440.050 ;
    END
  END s_axi_araddr_16
  PIN s_axi_araddr_17
    DIRECTION INPUT ;
    USE SIGNAL ;
    ANTENNAGATEAREA 0.647700 ;
    ANTENNADIFFAREA 0.434700 ;
    PORT
      LAYER met2 ;
        RECT 237.450 439.770 237.730 440.050 ;
    END
  END s_axi_araddr_17
  PIN s_axi_araddr_18
    DIRECTION INPUT ;
    USE SIGNAL ;
    ANTENNAGATEAREA 0.647700 ;
    ANTENNADIFFAREA 0.434700 ;
    PORT
      LAYER met2 ;
        RECT 236.530 439.770 236.810 440.050 ;
    END
  END s_axi_araddr_18
  PIN s_axi_araddr_19
    DIRECTION INPUT ;
    USE SIGNAL ;
    ANTENNAGATEAREA 0.647700 ;
    ANTENNADIFFAREA 0.434700 ;
    PORT
      LAYER met2 ;
        RECT 241.130 439.770 241.410 440.050 ;
    END
  END s_axi_araddr_19
  PIN s_axi_araddr_2
    DIRECTION INPUT ;
    USE SIGNAL ;
    ANTENNAGATEAREA 0.647700 ;
    ANTENNADIFFAREA 0.434700 ;
    PORT
      LAYER met2 ;
        RECT 281.610 439.770 281.890 440.050 ;
    END
  END s_axi_araddr_2
  PIN s_axi_araddr_20
    DIRECTION INPUT ;
    USE SIGNAL ;
    ANTENNAGATEAREA 0.647700 ;
    ANTENNADIFFAREA 0.434700 ;
    PORT
      LAYER met2 ;
        RECT 256.770 439.770 257.050 440.050 ;
    END
  END s_axi_araddr_20
  PIN s_axi_araddr_21
    DIRECTION INPUT ;
    USE SIGNAL ;
    ANTENNAGATEAREA 0.647700 ;
    ANTENNADIFFAREA 0.434700 ;
    PORT
      LAYER met2 ;
        RECT 212.610 439.770 212.890 440.050 ;
    END
  END s_axi_araddr_21
  PIN s_axi_araddr_22
    DIRECTION INPUT ;
    USE SIGNAL ;
    ANTENNAGATEAREA 0.647700 ;
    ANTENNADIFFAREA 0.434700 ;
    PORT
      LAYER met2 ;
        RECT 213.530 439.770 213.810 440.050 ;
    END
  END s_axi_araddr_22
  PIN s_axi_araddr_23
    DIRECTION INPUT ;
    USE SIGNAL ;
    ANTENNAGATEAREA 0.647700 ;
    ANTENNADIFFAREA 0.434700 ;
    PORT
      LAYER met2 ;
        RECT 260.450 439.770 260.730 440.050 ;
    END
  END s_axi_araddr_23
  PIN s_axi_araddr_24
    DIRECTION INPUT ;
    USE SIGNAL ;
    ANTENNAGATEAREA 0.647700 ;
    ANTENNADIFFAREA 0.434700 ;
    PORT
      LAYER met2 ;
        RECT 214.450 439.770 214.730 440.050 ;
    END
  END s_axi_araddr_24
  PIN s_axi_araddr_25
    DIRECTION INPUT ;
    USE SIGNAL ;
    ANTENNAGATEAREA 0.647700 ;
    ANTENNADIFFAREA 0.434700 ;
    PORT
      LAYER met2 ;
        RECT 216.290 439.770 216.570 440.050 ;
    END
  END s_axi_araddr_25
  PIN s_axi_araddr_26
    DIRECTION INPUT ;
    USE SIGNAL ;
    ANTENNAGATEAREA 0.647700 ;
    ANTENNADIFFAREA 0.434700 ;
    PORT
      LAYER met2 ;
        RECT 217.210 439.770 217.490 440.050 ;
    END
  END s_axi_araddr_26
  PIN s_axi_araddr_27
    DIRECTION INPUT ;
    USE SIGNAL ;
    ANTENNAGATEAREA 0.647700 ;
    ANTENNADIFFAREA 0.434700 ;
    PORT
      LAYER met2 ;
        RECT 252.170 439.770 252.450 440.050 ;
    END
  END s_axi_araddr_27
  PIN s_axi_araddr_28
    DIRECTION INPUT ;
    USE SIGNAL ;
    ANTENNAGATEAREA 0.647700 ;
    ANTENNADIFFAREA 0.434700 ;
    PORT
      LAYER met2 ;
        RECT 211.690 439.770 211.970 440.050 ;
    END
  END s_axi_araddr_28
  PIN s_axi_araddr_29
    DIRECTION INPUT ;
    USE SIGNAL ;
    ANTENNAGATEAREA 0.647700 ;
    ANTENNADIFFAREA 0.434700 ;
    PORT
      LAYER met2 ;
        RECT 261.370 439.770 261.650 440.050 ;
    END
  END s_axi_araddr_29
  PIN s_axi_araddr_3
    DIRECTION INPUT ;
    USE SIGNAL ;
    ANTENNAGATEAREA 0.647700 ;
    ANTENNADIFFAREA 0.434700 ;
    PORT
      LAYER met2 ;
        RECT 265.050 439.770 265.330 440.050 ;
    END
  END s_axi_araddr_3
  PIN s_axi_araddr_30
    DIRECTION INPUT ;
    USE SIGNAL ;
    ANTENNAGATEAREA 0.647700 ;
    ANTENNADIFFAREA 0.434700 ;
    PORT
      LAYER met2 ;
        RECT 210.770 439.770 211.050 440.050 ;
    END
  END s_axi_araddr_30
  PIN s_axi_araddr_31
    DIRECTION INPUT ;
    USE SIGNAL ;
    ANTENNAGATEAREA 0.647700 ;
    ANTENNADIFFAREA 0.434700 ;
    PORT
      LAYER met2 ;
        RECT 244.810 439.770 245.090 440.050 ;
    END
  END s_axi_araddr_31
  PIN s_axi_araddr_4
    DIRECTION INPUT ;
    USE SIGNAL ;
    ANTENNAGATEAREA 0.647700 ;
    ANTENNADIFFAREA 0.434700 ;
    PORT
      LAYER met2 ;
        RECT 287.130 439.770 287.410 440.050 ;
    END
  END s_axi_araddr_4
  PIN s_axi_araddr_5
    DIRECTION INPUT ;
    USE SIGNAL ;
    ANTENNAGATEAREA 0.647700 ;
    ANTENNADIFFAREA 0.434700 ;
    PORT
      LAYER met2 ;
        RECT 288.970 439.770 289.250 440.050 ;
    END
  END s_axi_araddr_5
  PIN s_axi_araddr_6
    DIRECTION INPUT ;
    USE SIGNAL ;
    ANTENNAGATEAREA 0.647700 ;
    ANTENNADIFFAREA 0.434700 ;
    PORT
      LAYER met2 ;
        RECT 275.170 439.770 275.450 440.050 ;
    END
  END s_axi_araddr_6
  PIN s_axi_araddr_7
    DIRECTION INPUT ;
    USE SIGNAL ;
    ANTENNAGATEAREA 0.647700 ;
    ANTENNADIFFAREA 0.434700 ;
    PORT
      LAYER met2 ;
        RECT 262.290 439.770 262.570 440.050 ;
    END
  END s_axi_araddr_7
  PIN s_axi_araddr_8
    DIRECTION INPUT ;
    USE SIGNAL ;
    ANTENNAGATEAREA 0.647700 ;
    ANTENNADIFFAREA 0.434700 ;
    PORT
      LAYER met2 ;
        RECT 280.690 439.770 280.970 440.050 ;
    END
  END s_axi_araddr_8
  PIN s_axi_araddr_9
    DIRECTION INPUT ;
    USE SIGNAL ;
    ANTENNAGATEAREA 0.647700 ;
    ANTENNADIFFAREA 0.434700 ;
    PORT
      LAYER met2 ;
        RECT 278.850 439.770 279.130 440.050 ;
    END
  END s_axi_araddr_9
  PIN s_axi_arready
    DIRECTION OUTPUT ;
    USE SIGNAL ;
    ANTENNAGATEAREA 0.434700 ;
    ANTENNADIFFAREA 1.137600 ;
    PORT
      LAYER met2 ;
        RECT 185.930 0.000 186.210 0.280 ;
    END
  END s_axi_arready
  PIN s_axi_arvalid
    DIRECTION INPUT ;
    USE SIGNAL ;
    ANTENNAGATEAREA 0.647700 ;
    ANTENNADIFFAREA 0.434700 ;
    PORT
      LAYER met2 ;
        RECT 240.210 439.770 240.490 440.050 ;
    END
  END s_axi_arvalid
  PIN s_axi_awaddr_0
    DIRECTION INPUT ;
    USE SIGNAL ;
    ANTENNAGATEAREA 0.647700 ;
    ANTENNADIFFAREA 0.434700 ;
    PORT
      LAYER met3 ;
        RECT 428.730 282.920 429.330 283.520 ;
    END
  END s_axi_awaddr_0
  PIN s_axi_awaddr_1
    DIRECTION INPUT ;
    USE SIGNAL ;
    ANTENNAGATEAREA 0.647700 ;
    ANTENNADIFFAREA 0.434700 ;
    PORT
      LAYER met3 ;
        RECT 428.730 232.600 429.330 233.200 ;
    END
  END s_axi_awaddr_1
  PIN s_axi_awaddr_10
    DIRECTION INPUT ;
    USE SIGNAL ;
    ANTENNAGATEAREA 0.647700 ;
    ANTENNADIFFAREA 0.434700 ;
    PORT
      LAYER met3 ;
        RECT 428.730 276.120 429.330 276.720 ;
    END
  END s_axi_awaddr_10
  PIN s_axi_awaddr_11
    DIRECTION INPUT ;
    USE SIGNAL ;
    ANTENNAGATEAREA 0.647700 ;
    ANTENNADIFFAREA 0.434700 ;
    PORT
      LAYER met3 ;
        RECT 428.730 281.560 429.330 282.160 ;
    END
  END s_axi_awaddr_11
  PIN s_axi_awaddr_12
    DIRECTION INPUT ;
    USE SIGNAL ;
    ANTENNAGATEAREA 0.647700 ;
    ANTENNADIFFAREA 0.434700 ;
    PORT
      LAYER met3 ;
        RECT 428.730 273.400 429.330 274.000 ;
    END
  END s_axi_awaddr_12
  PIN s_axi_awaddr_13
    DIRECTION INPUT ;
    USE SIGNAL ;
    ANTENNAGATEAREA 0.647700 ;
    ANTENNADIFFAREA 0.434700 ;
    PORT
      LAYER met3 ;
        RECT 428.730 293.800 429.330 294.400 ;
    END
  END s_axi_awaddr_13
  PIN s_axi_awaddr_14
    DIRECTION INPUT ;
    USE SIGNAL ;
    ANTENNAGATEAREA 0.647700 ;
    ANTENNADIFFAREA 0.434700 ;
    PORT
      LAYER met3 ;
        RECT 428.730 303.320 429.330 303.920 ;
    END
  END s_axi_awaddr_14
  PIN s_axi_awaddr_15
    DIRECTION INPUT ;
    USE SIGNAL ;
    ANTENNAGATEAREA 0.647700 ;
    ANTENNADIFFAREA 0.434700 ;
    PORT
      LAYER met3 ;
        RECT 428.730 325.080 429.330 325.680 ;
    END
  END s_axi_awaddr_15
  PIN s_axi_awaddr_16
    DIRECTION INPUT ;
    USE SIGNAL ;
    ANTENNAGATEAREA 0.647700 ;
    ANTENNADIFFAREA 0.434700 ;
    PORT
      LAYER met3 ;
        RECT 428.730 311.480 429.330 312.080 ;
    END
  END s_axi_awaddr_16
  PIN s_axi_awaddr_17
    DIRECTION INPUT ;
    USE SIGNAL ;
    ANTENNAGATEAREA 0.647700 ;
    ANTENNADIFFAREA 0.434700 ;
    PORT
      LAYER met3 ;
        RECT 428.730 333.240 429.330 333.840 ;
    END
  END s_axi_awaddr_17
  PIN s_axi_awaddr_18
    DIRECTION INPUT ;
    USE SIGNAL ;
    ANTENNAGATEAREA 0.647700 ;
    ANTENNADIFFAREA 0.434700 ;
    PORT
      LAYER met3 ;
        RECT 428.730 301.960 429.330 302.560 ;
    END
  END s_axi_awaddr_18
  PIN s_axi_awaddr_19
    DIRECTION INPUT ;
    USE SIGNAL ;
    ANTENNAGATEAREA 0.647700 ;
    ANTENNADIFFAREA 0.434700 ;
    PORT
      LAYER met3 ;
        RECT 428.730 318.280 429.330 318.880 ;
    END
  END s_axi_awaddr_19
  PIN s_axi_awaddr_2
    DIRECTION INPUT ;
    USE SIGNAL ;
    ANTENNAGATEAREA 0.647700 ;
    ANTENNADIFFAREA 0.434700 ;
    PORT
      LAYER met3 ;
        RECT 428.730 239.400 429.330 240.000 ;
    END
  END s_axi_awaddr_2
  PIN s_axi_awaddr_20
    DIRECTION INPUT ;
    USE SIGNAL ;
    ANTENNAGATEAREA 0.647700 ;
    ANTENNADIFFAREA 0.434700 ;
    PORT
      LAYER met3 ;
        RECT 428.730 307.400 429.330 308.000 ;
    END
  END s_axi_awaddr_20
  PIN s_axi_awaddr_21
    DIRECTION INPUT ;
    USE SIGNAL ;
    ANTENNAGATEAREA 0.647700 ;
    ANTENNADIFFAREA 0.434700 ;
    PORT
      LAYER met3 ;
        RECT 428.730 289.720 429.330 290.320 ;
    END
  END s_axi_awaddr_21
  PIN s_axi_awaddr_22
    DIRECTION INPUT ;
    USE SIGNAL ;
    ANTENNAGATEAREA 0.647700 ;
    ANTENNADIFFAREA 0.434700 ;
    PORT
      LAYER met3 ;
        RECT 428.730 342.760 429.330 343.360 ;
    END
  END s_axi_awaddr_22
  PIN s_axi_awaddr_23
    DIRECTION INPUT ;
    USE SIGNAL ;
    ANTENNAGATEAREA 0.647700 ;
    ANTENNADIFFAREA 0.434700 ;
    PORT
      LAYER met3 ;
        RECT 428.730 321.000 429.330 321.600 ;
    END
  END s_axi_awaddr_23
  PIN s_axi_awaddr_24
    DIRECTION INPUT ;
    USE SIGNAL ;
    ANTENNAGATEAREA 0.647700 ;
    ANTENNADIFFAREA 0.434700 ;
    PORT
      LAYER met3 ;
        RECT 428.730 337.320 429.330 337.920 ;
    END
  END s_axi_awaddr_24
  PIN s_axi_awaddr_25
    DIRECTION INPUT ;
    USE SIGNAL ;
    ANTENNAGATEAREA 0.647700 ;
    ANTENNADIFFAREA 0.434700 ;
    PORT
      LAYER met3 ;
        RECT 428.730 335.960 429.330 336.560 ;
    END
  END s_axi_awaddr_25
  PIN s_axi_awaddr_26
    DIRECTION INPUT ;
    USE SIGNAL ;
    ANTENNAGATEAREA 0.647700 ;
    ANTENNADIFFAREA 0.434700 ;
    PORT
      LAYER met3 ;
        RECT 428.730 314.200 429.330 314.800 ;
    END
  END s_axi_awaddr_26
  PIN s_axi_awaddr_27
    DIRECTION INPUT ;
    USE SIGNAL ;
    ANTENNAGATEAREA 0.647700 ;
    ANTENNADIFFAREA 0.434700 ;
    PORT
      LAYER met3 ;
        RECT 428.730 292.440 429.330 293.040 ;
    END
  END s_axi_awaddr_27
  PIN s_axi_awaddr_28
    DIRECTION INPUT ;
    USE SIGNAL ;
    ANTENNAGATEAREA 0.647700 ;
    ANTENNADIFFAREA 0.434700 ;
    PORT
      LAYER met3 ;
        RECT 428.730 288.360 429.330 288.960 ;
    END
  END s_axi_awaddr_28
  PIN s_axi_awaddr_29
    DIRECTION INPUT ;
    USE SIGNAL ;
    ANTENNAGATEAREA 0.647700 ;
    ANTENNADIFFAREA 0.434700 ;
    PORT
      LAYER met3 ;
        RECT 428.730 334.600 429.330 335.200 ;
    END
  END s_axi_awaddr_29
  PIN s_axi_awaddr_3
    DIRECTION INPUT ;
    USE SIGNAL ;
    ANTENNAGATEAREA 0.647700 ;
    ANTENNADIFFAREA 0.434700 ;
    PORT
      LAYER met3 ;
        RECT 428.730 274.760 429.330 275.360 ;
    END
  END s_axi_awaddr_3
  PIN s_axi_awaddr_30
    DIRECTION INPUT ;
    USE SIGNAL ;
    ANTENNAGATEAREA 0.647700 ;
    ANTENNADIFFAREA 0.434700 ;
    PORT
      LAYER met3 ;
        RECT 428.730 310.120 429.330 310.720 ;
    END
  END s_axi_awaddr_30
  PIN s_axi_awaddr_31
    DIRECTION INPUT ;
    USE SIGNAL ;
    ANTENNAGATEAREA 0.647700 ;
    ANTENNADIFFAREA 0.434700 ;
    PORT
      LAYER met3 ;
        RECT 428.730 341.400 429.330 342.000 ;
    END
  END s_axi_awaddr_31
  PIN s_axi_awaddr_4
    DIRECTION INPUT ;
    USE SIGNAL ;
    ANTENNAGATEAREA 0.647700 ;
    ANTENNADIFFAREA 0.434700 ;
    PORT
      LAYER met3 ;
        RECT 428.730 280.200 429.330 280.800 ;
    END
  END s_axi_awaddr_4
  PIN s_axi_awaddr_5
    DIRECTION INPUT ;
    USE SIGNAL ;
    ANTENNAGATEAREA 0.647700 ;
    ANTENNADIFFAREA 0.434700 ;
    PORT
      LAYER met3 ;
        RECT 428.730 233.960 429.330 234.560 ;
    END
  END s_axi_awaddr_5
  PIN s_axi_awaddr_6
    DIRECTION INPUT ;
    USE SIGNAL ;
    ANTENNAGATEAREA 0.647700 ;
    ANTENNADIFFAREA 0.434700 ;
    PORT
      LAYER met3 ;
        RECT 428.730 277.480 429.330 278.080 ;
    END
  END s_axi_awaddr_6
  PIN s_axi_awaddr_7
    DIRECTION INPUT ;
    USE SIGNAL ;
    ANTENNAGATEAREA 0.647700 ;
    ANTENNADIFFAREA 0.434700 ;
    PORT
      LAYER met3 ;
        RECT 428.730 240.760 429.330 241.360 ;
    END
  END s_axi_awaddr_7
  PIN s_axi_awaddr_8
    DIRECTION INPUT ;
    USE SIGNAL ;
    ANTENNAGATEAREA 0.647700 ;
    ANTENNADIFFAREA 0.434700 ;
    PORT
      LAYER met3 ;
        RECT 428.730 231.240 429.330 231.840 ;
    END
  END s_axi_awaddr_8
  PIN s_axi_awaddr_9
    DIRECTION INPUT ;
    USE SIGNAL ;
    ANTENNAGATEAREA 0.647700 ;
    ANTENNADIFFAREA 0.434700 ;
    PORT
      LAYER met3 ;
        RECT 428.730 278.840 429.330 279.440 ;
    END
  END s_axi_awaddr_9
  PIN s_axi_awready
    DIRECTION OUTPUT ;
    USE SIGNAL ;
    ANTENNAGATEAREA 0.434700 ;
    ANTENNADIFFAREA 1.137600 ;
    PORT
      LAYER met3 ;
        RECT 428.730 340.040 429.330 340.640 ;
    END
  END s_axi_awready
  PIN s_axi_awvalid
    DIRECTION INPUT ;
    USE SIGNAL ;
    ANTENNAGATEAREA 0.647700 ;
    ANTENNADIFFAREA 0.434700 ;
    PORT
      LAYER met3 ;
        RECT 428.730 338.680 429.330 339.280 ;
    END
  END s_axi_awvalid
  PIN s_axi_bready
    DIRECTION INPUT ;
    USE SIGNAL ;
    ANTENNAGATEAREA 0.647700 ;
    ANTENNADIFFAREA 0.434700 ;
    PORT
      LAYER met2 ;
        RECT 338.650 439.770 338.930 440.050 ;
    END
  END s_axi_bready
  PIN s_axi_bresp_0
    DIRECTION OUTPUT ;
    USE SIGNAL ;
    ANTENNAGATEAREA 0.434700 ;
    ANTENNADIFFAREA 0.434700 ;
    PORT
      LAYER met3 ;
        RECT 0.000 314.200 0.600 314.800 ;
    END
  END s_axi_bresp_0
  PIN s_axi_bresp_1
    DIRECTION OUTPUT ;
    USE SIGNAL ;
    ANTENNAGATEAREA 0.434700 ;
    ANTENNADIFFAREA 0.775300 ;
    PORT
      LAYER met3 ;
        RECT 0.000 310.120 0.600 310.720 ;
    END
  END s_axi_bresp_1
  PIN s_axi_bvalid
    DIRECTION OUTPUT ;
    USE SIGNAL ;
    ANTENNAGATEAREA 0.434700 ;
    ANTENNADIFFAREA 1.137600 ;
    PORT
      LAYER met2 ;
        RECT 339.570 439.770 339.850 440.050 ;
    END
  END s_axi_bvalid
  PIN s_axi_rdata_0
    DIRECTION OUTPUT ;
    USE SIGNAL ;
    ANTENNAGATEAREA 0.434700 ;
    ANTENNADIFFAREA 1.137600 ;
    PORT
      LAYER met2 ;
        RECT 179.490 439.770 179.770 440.050 ;
    END
  END s_axi_rdata_0
  PIN s_axi_rdata_1
    DIRECTION OUTPUT ;
    USE SIGNAL ;
    ANTENNAGATEAREA 0.434700 ;
    ANTENNADIFFAREA 1.137600 ;
    PORT
      LAYER met2 ;
        RECT 272.410 439.770 272.690 440.050 ;
    END
  END s_axi_rdata_1
  PIN s_axi_rdata_10
    DIRECTION OUTPUT ;
    USE SIGNAL ;
    ANTENNAGATEAREA 0.434700 ;
    ANTENNADIFFAREA 1.137600 ;
    PORT
      LAYER met2 ;
        RECT 239.290 0.000 239.570 0.280 ;
    END
  END s_axi_rdata_10
  PIN s_axi_rdata_11
    DIRECTION OUTPUT ;
    USE SIGNAL ;
    ANTENNAGATEAREA 0.434700 ;
    ANTENNADIFFAREA 1.137600 ;
    PORT
      LAYER met2 ;
        RECT 278.850 0.000 279.130 0.280 ;
    END
  END s_axi_rdata_11
  PIN s_axi_rdata_12
    DIRECTION OUTPUT ;
    USE SIGNAL ;
    ANTENNAGATEAREA 0.434700 ;
    ANTENNADIFFAREA 1.137600 ;
    PORT
      LAYER met2 ;
        RECT 225.490 0.000 225.770 0.280 ;
    END
  END s_axi_rdata_12
  PIN s_axi_rdata_13
    DIRECTION OUTPUT ;
    USE SIGNAL ;
    ANTENNAGATEAREA 0.434700 ;
    ANTENNADIFFAREA 1.137600 ;
    PORT
      LAYER met3 ;
        RECT 428.730 175.480 429.330 176.080 ;
    END
  END s_axi_rdata_13
  PIN s_axi_rdata_14
    DIRECTION OUTPUT ;
    USE SIGNAL ;
    ANTENNAGATEAREA 0.434700 ;
    ANTENNADIFFAREA 1.137600 ;
    PORT
      LAYER met2 ;
        RECT 170.290 0.000 170.570 0.280 ;
    END
  END s_axi_rdata_14
  PIN s_axi_rdata_15
    DIRECTION OUTPUT ;
    USE SIGNAL ;
    ANTENNAGATEAREA 0.434700 ;
    ANTENNADIFFAREA 1.137600 ;
    PORT
      LAYER met2 ;
        RECT 194.210 0.000 194.490 0.280 ;
    END
  END s_axi_rdata_15
  PIN s_axi_rdata_16
    DIRECTION OUTPUT ;
    USE SIGNAL ;
    ANTENNAGATEAREA 0.434700 ;
    ANTENNADIFFAREA 1.137600 ;
    PORT
      LAYER met2 ;
        RECT 310.130 0.000 310.410 0.280 ;
    END
  END s_axi_rdata_16
  PIN s_axi_rdata_17
    DIRECTION OUTPUT ;
    USE SIGNAL ;
    ANTENNAGATEAREA 0.434700 ;
    ANTENNADIFFAREA 1.137600 ;
    PORT
      LAYER met2 ;
        RECT 304.610 0.000 304.890 0.280 ;
    END
  END s_axi_rdata_17
  PIN s_axi_rdata_18
    DIRECTION OUTPUT ;
    USE SIGNAL ;
    ANTENNAGATEAREA 0.434700 ;
    ANTENNADIFFAREA 1.137600 ;
    PORT
      LAYER met3 ;
        RECT 428.730 213.560 429.330 214.160 ;
    END
  END s_axi_rdata_18
  PIN s_axi_rdata_19
    DIRECTION OUTPUT ;
    USE SIGNAL ;
    ANTENNAGATEAREA 0.434700 ;
    ANTENNADIFFAREA 1.137600 ;
    PORT
      LAYER met2 ;
        RECT 242.050 0.000 242.330 0.280 ;
    END
  END s_axi_rdata_19
  PIN s_axi_rdata_2
    DIRECTION OUTPUT ;
    USE SIGNAL ;
    ANTENNAGATEAREA 0.434700 ;
    ANTENNADIFFAREA 1.137600 ;
    PORT
      LAYER met2 ;
        RECT 175.810 439.770 176.090 440.050 ;
    END
  END s_axi_rdata_2
  PIN s_axi_rdata_20
    DIRECTION OUTPUT ;
    USE SIGNAL ;
    ANTENNAGATEAREA 0.434700 ;
    ANTENNADIFFAREA 1.137600 ;
    PORT
      LAYER met2 ;
        RECT 325.770 0.000 326.050 0.280 ;
    END
  END s_axi_rdata_20
  PIN s_axi_rdata_21
    DIRECTION OUTPUT ;
    USE SIGNAL ;
    ANTENNAGATEAREA 0.434700 ;
    ANTENNADIFFAREA 1.137600 ;
    PORT
      LAYER met2 ;
        RECT 262.290 0.000 262.570 0.280 ;
    END
  END s_axi_rdata_21
  PIN s_axi_rdata_22
    DIRECTION OUTPUT ;
    USE SIGNAL ;
    ANTENNAGATEAREA 0.434700 ;
    ANTENNADIFFAREA 1.137600 ;
    PORT
      LAYER met2 ;
        RECT 202.490 439.770 202.770 440.050 ;
    END
  END s_axi_rdata_22
  PIN s_axi_rdata_23
    DIRECTION OUTPUT ;
    USE SIGNAL ;
    ANTENNAGATEAREA 0.434700 ;
    ANTENNADIFFAREA 1.137600 ;
    PORT
      LAYER met2 ;
        RECT 329.450 439.770 329.730 440.050 ;
    END
  END s_axi_rdata_23
  PIN s_axi_rdata_24
    DIRECTION OUTPUT ;
    USE SIGNAL ;
    ANTENNAGATEAREA 0.434700 ;
    ANTENNADIFFAREA 1.137600 ;
    PORT
      LAYER met3 ;
        RECT 428.730 168.680 429.330 169.280 ;
    END
  END s_axi_rdata_24
  PIN s_axi_rdata_25
    DIRECTION OUTPUT ;
    USE SIGNAL ;
    ANTENNAGATEAREA 0.434700 ;
    ANTENNADIFFAREA 1.137600 ;
    PORT
      LAYER met3 ;
        RECT 428.730 130.600 429.330 131.200 ;
    END
  END s_axi_rdata_25
  PIN s_axi_rdata_26
    DIRECTION OUTPUT ;
    USE SIGNAL ;
    ANTENNAGATEAREA 0.434700 ;
    ANTENNADIFFAREA 1.137600 ;
    PORT
      LAYER met2 ;
        RECT 261.370 0.000 261.650 0.280 ;
    END
  END s_axi_rdata_26
  PIN s_axi_rdata_27
    DIRECTION OUTPUT ;
    USE SIGNAL ;
    ANTENNAGATEAREA 0.434700 ;
    ANTENNADIFFAREA 1.137600 ;
    PORT
      LAYER met3 ;
        RECT 428.730 136.040 429.330 136.640 ;
    END
  END s_axi_rdata_27
  PIN s_axi_rdata_28
    DIRECTION OUTPUT ;
    USE SIGNAL ;
    ANTENNAGATEAREA 0.434700 ;
    ANTENNADIFFAREA 1.137600 ;
    PORT
      LAYER met2 ;
        RECT 328.530 439.770 328.810 440.050 ;
    END
  END s_axi_rdata_28
  PIN s_axi_rdata_29
    DIRECTION OUTPUT ;
    USE SIGNAL ;
    ANTENNAGATEAREA 0.434700 ;
    ANTENNADIFFAREA 1.137600 ;
    PORT
      LAYER met2 ;
        RECT 232.850 439.770 233.130 440.050 ;
    END
  END s_axi_rdata_29
  PIN s_axi_rdata_3
    DIRECTION OUTPUT ;
    USE SIGNAL ;
    ANTENNAGATEAREA 0.434700 ;
    ANTENNADIFFAREA 1.137600 ;
    PORT
      LAYER met2 ;
        RECT 231.010 439.770 231.290 440.050 ;
    END
  END s_axi_rdata_3
  PIN s_axi_rdata_30
    DIRECTION OUTPUT ;
    USE SIGNAL ;
    ANTENNAGATEAREA 0.434700 ;
    ANTENNADIFFAREA 1.137600 ;
    PORT
      LAYER met2 ;
        RECT 327.610 439.770 327.890 440.050 ;
    END
  END s_axi_rdata_30
  PIN s_axi_rdata_31
    DIRECTION OUTPUT ;
    USE SIGNAL ;
    ANTENNAGATEAREA 0.434700 ;
    ANTENNADIFFAREA 1.137600 ;
    PORT
      LAYER met2 ;
        RECT 201.570 439.770 201.850 440.050 ;
    END
  END s_axi_rdata_31
  PIN s_axi_rdata_4
    DIRECTION OUTPUT ;
    USE SIGNAL ;
    ANTENNAGATEAREA 0.434700 ;
    ANTENNADIFFAREA 1.137600 ;
    PORT
      LAYER met2 ;
        RECT 173.050 0.000 173.330 0.280 ;
    END
  END s_axi_rdata_4
  PIN s_axi_rdata_5
    DIRECTION OUTPUT ;
    USE SIGNAL ;
    ANTENNAGATEAREA 0.434700 ;
    ANTENNADIFFAREA 1.137600 ;
    PORT
      LAYER met2 ;
        RECT 173.970 0.000 174.250 0.280 ;
    END
  END s_axi_rdata_5
  PIN s_axi_rdata_6
    DIRECTION OUTPUT ;
    USE SIGNAL ;
    ANTENNAGATEAREA 0.434700 ;
    ANTENNADIFFAREA 1.137600 ;
    PORT
      LAYER met2 ;
        RECT 265.050 0.000 265.330 0.280 ;
    END
  END s_axi_rdata_6
  PIN s_axi_rdata_7
    DIRECTION OUTPUT ;
    USE SIGNAL ;
    ANTENNAGATEAREA 0.434700 ;
    ANTENNADIFFAREA 1.137600 ;
    PORT
      LAYER met3 ;
        RECT 428.730 235.320 429.330 235.920 ;
    END
  END s_axi_rdata_7
  PIN s_axi_rdata_8
    DIRECTION OUTPUT ;
    USE SIGNAL ;
    ANTENNAGATEAREA 0.434700 ;
    ANTENNADIFFAREA 1.137600 ;
    PORT
      LAYER met2 ;
        RECT 188.690 439.770 188.970 440.050 ;
    END
  END s_axi_rdata_8
  PIN s_axi_rdata_9
    DIRECTION OUTPUT ;
    USE SIGNAL ;
    ANTENNAGATEAREA 0.434700 ;
    ANTENNADIFFAREA 1.137600 ;
    PORT
      LAYER met2 ;
        RECT 172.130 439.770 172.410 440.050 ;
    END
  END s_axi_rdata_9
  PIN s_axi_rready
    DIRECTION INPUT ;
    USE SIGNAL ;
    ANTENNAGATEAREA 0.647700 ;
    ANTENNADIFFAREA 0.434700 ;
    PORT
      LAYER met2 ;
        RECT 238.370 439.770 238.650 440.050 ;
    END
  END s_axi_rready
  PIN s_axi_rresp_0
    DIRECTION OUTPUT ;
    USE SIGNAL ;
    ANTENNAGATEAREA 0.434700 ;
    ANTENNADIFFAREA 0.775300 ;
    PORT
      LAYER met3 ;
        RECT 0.000 307.400 0.600 308.000 ;
    END
  END s_axi_rresp_0
  PIN s_axi_rresp_1
    DIRECTION OUTPUT ;
    USE SIGNAL ;
    ANTENNAGATEAREA 0.434700 ;
    ANTENNADIFFAREA 0.775300 ;
    PORT
      LAYER met3 ;
        RECT 0.000 308.760 0.600 309.360 ;
    END
  END s_axi_rresp_1
  PIN s_axi_rvalid
    DIRECTION OUTPUT ;
    USE SIGNAL ;
    ANTENNAGATEAREA 0.434700 ;
    ANTENNADIFFAREA 1.137600 ;
    PORT
      LAYER met2 ;
        RECT 242.050 439.770 242.330 440.050 ;
    END
  END s_axi_rvalid
  PIN s_axi_wdata_0
    DIRECTION INPUT ;
    USE SIGNAL ;
    ANTENNAGATEAREA 0.647700 ;
    ANTENNADIFFAREA 0.434700 ;
    PORT
      LAYER met2 ;
        RECT 331.290 439.770 331.570 440.050 ;
    END
  END s_axi_wdata_0
  PIN s_axi_wdata_1
    DIRECTION INPUT ;
    USE SIGNAL ;
    ANTENNAGATEAREA 0.647700 ;
    ANTENNADIFFAREA 0.434700 ;
    PORT
      LAYER met2 ;
        RECT 308.290 439.770 308.570 440.050 ;
    END
  END s_axi_wdata_1
  PIN s_axi_wdata_10
    DIRECTION INPUT ;
    USE SIGNAL ;
    ANTENNAGATEAREA 0.647700 ;
    ANTENNADIFFAREA 0.434700 ;
    PORT
      LAYER met2 ;
        RECT 311.050 439.770 311.330 440.050 ;
    END
  END s_axi_wdata_10
  PIN s_axi_wdata_11
    DIRECTION INPUT ;
    USE SIGNAL ;
    ANTENNAGATEAREA 0.647700 ;
    ANTENNADIFFAREA 0.434700 ;
    PORT
      LAYER met2 ;
        RECT 357.970 439.770 358.250 440.050 ;
    END
  END s_axi_wdata_11
  PIN s_axi_wdata_12
    DIRECTION INPUT ;
    USE SIGNAL ;
    ANTENNAGATEAREA 0.647700 ;
    ANTENNADIFFAREA 0.434700 ;
    PORT
      LAYER met3 ;
        RECT 428.730 387.640 429.330 388.240 ;
    END
  END s_axi_wdata_12
  PIN s_axi_wdata_13
    DIRECTION INPUT ;
    USE SIGNAL ;
    ANTENNAGATEAREA 0.647700 ;
    ANTENNADIFFAREA 0.434700 ;
    PORT
      LAYER met2 ;
        RECT 355.210 439.770 355.490 440.050 ;
    END
  END s_axi_wdata_13
  PIN s_axi_wdata_14
    DIRECTION INPUT ;
    USE SIGNAL ;
    ANTENNAGATEAREA 0.647700 ;
    ANTENNADIFFAREA 0.434700 ;
    PORT
      LAYER met3 ;
        RECT 428.730 384.920 429.330 385.520 ;
    END
  END s_axi_wdata_14
  PIN s_axi_wdata_15
    DIRECTION INPUT ;
    USE SIGNAL ;
    ANTENNAGATEAREA 0.647700 ;
    ANTENNADIFFAREA 0.434700 ;
    PORT
      LAYER met3 ;
        RECT 428.730 365.880 429.330 366.480 ;
    END
  END s_axi_wdata_15
  PIN s_axi_wdata_16
    DIRECTION INPUT ;
    USE SIGNAL ;
    ANTENNAGATEAREA 0.647700 ;
    ANTENNADIFFAREA 0.434700 ;
    PORT
      LAYER met3 ;
        RECT 428.730 363.160 429.330 363.760 ;
    END
  END s_axi_wdata_16
  PIN s_axi_wdata_17
    DIRECTION INPUT ;
    USE SIGNAL ;
    ANTENNAGATEAREA 0.647700 ;
    ANTENNADIFFAREA 0.434700 ;
    PORT
      LAYER met2 ;
        RECT 310.130 439.770 310.410 440.050 ;
    END
  END s_axi_wdata_17
  PIN s_axi_wdata_18
    DIRECTION INPUT ;
    USE SIGNAL ;
    ANTENNAGATEAREA 0.647700 ;
    ANTENNADIFFAREA 0.434700 ;
    PORT
      LAYER met2 ;
        RECT 309.210 439.770 309.490 440.050 ;
    END
  END s_axi_wdata_18
  PIN s_axi_wdata_19
    DIRECTION INPUT ;
    USE SIGNAL ;
    ANTENNAGATEAREA 0.647700 ;
    ANTENNADIFFAREA 0.434700 ;
    PORT
      LAYER met2 ;
        RECT 320.250 439.770 320.530 440.050 ;
    END
  END s_axi_wdata_19
  PIN s_axi_wdata_2
    DIRECTION INPUT ;
    USE SIGNAL ;
    ANTENNAGATEAREA 0.647700 ;
    ANTENNADIFFAREA 0.434700 ;
    PORT
      LAYER met3 ;
        RECT 428.730 361.800 429.330 362.400 ;
    END
  END s_axi_wdata_2
  PIN s_axi_wdata_20
    DIRECTION INPUT ;
    USE SIGNAL ;
    ANTENNAGATEAREA 0.647700 ;
    ANTENNADIFFAREA 0.434700 ;
    PORT
      LAYER met3 ;
        RECT 428.730 359.080 429.330 359.680 ;
    END
  END s_axi_wdata_20
  PIN s_axi_wdata_21
    DIRECTION INPUT ;
    USE SIGNAL ;
    ANTENNAGATEAREA 0.647700 ;
    ANTENNADIFFAREA 0.434700 ;
    PORT
      LAYER met3 ;
        RECT 428.730 356.360 429.330 356.960 ;
    END
  END s_axi_wdata_21
  PIN s_axi_wdata_22
    DIRECTION INPUT ;
    USE SIGNAL ;
    ANTENNAGATEAREA 0.647700 ;
    ANTENNADIFFAREA 0.434700 ;
    PORT
      LAYER met2 ;
        RECT 382.810 439.770 383.090 440.050 ;
    END
  END s_axi_wdata_22
  PIN s_axi_wdata_23
    DIRECTION INPUT ;
    USE SIGNAL ;
    ANTENNAGATEAREA 0.647700 ;
    ANTENNADIFFAREA 0.434700 ;
    PORT
      LAYER met2 ;
        RECT 354.290 439.770 354.570 440.050 ;
    END
  END s_axi_wdata_23
  PIN s_axi_wdata_24
    DIRECTION INPUT ;
    USE SIGNAL ;
    ANTENNAGATEAREA 0.647700 ;
    ANTENNADIFFAREA 0.434700 ;
    PORT
      LAYER met2 ;
        RECT 334.050 439.770 334.330 440.050 ;
    END
  END s_axi_wdata_24
  PIN s_axi_wdata_25
    DIRECTION INPUT ;
    USE SIGNAL ;
    ANTENNAGATEAREA 0.647700 ;
    ANTENNADIFFAREA 0.434700 ;
    PORT
      LAYER met3 ;
        RECT 428.730 364.520 429.330 365.120 ;
    END
  END s_axi_wdata_25
  PIN s_axi_wdata_26
    DIRECTION INPUT ;
    USE SIGNAL ;
    ANTENNAGATEAREA 0.647700 ;
    ANTENNADIFFAREA 0.434700 ;
    PORT
      LAYER met3 ;
        RECT 428.730 360.440 429.330 361.040 ;
    END
  END s_axi_wdata_26
  PIN s_axi_wdata_27
    DIRECTION INPUT ;
    USE SIGNAL ;
    ANTENNAGATEAREA 0.647700 ;
    ANTENNADIFFAREA 0.434700 ;
    PORT
      LAYER met2 ;
        RECT 312.890 439.770 313.170 440.050 ;
    END
  END s_axi_wdata_27
  PIN s_axi_wdata_28
    DIRECTION INPUT ;
    USE SIGNAL ;
    ANTENNAGATEAREA 0.647700 ;
    ANTENNADIFFAREA 0.434700 ;
    PORT
      LAYER met2 ;
        RECT 333.130 439.770 333.410 440.050 ;
    END
  END s_axi_wdata_28
  PIN s_axi_wdata_29
    DIRECTION INPUT ;
    USE SIGNAL ;
    ANTENNAGATEAREA 0.647700 ;
    ANTENNADIFFAREA 0.434700 ;
    PORT
      LAYER met2 ;
        RECT 369.930 439.770 370.210 440.050 ;
    END
  END s_axi_wdata_29
  PIN s_axi_wdata_3
    DIRECTION INPUT ;
    USE SIGNAL ;
    ANTENNAGATEAREA 0.647700 ;
    ANTENNADIFFAREA 0.434700 ;
    PORT
      LAYER met3 ;
        RECT 428.730 382.200 429.330 382.800 ;
    END
  END s_axi_wdata_3
  PIN s_axi_wdata_30
    DIRECTION INPUT ;
    USE SIGNAL ;
    ANTENNAGATEAREA 0.647700 ;
    ANTENNADIFFAREA 0.434700 ;
    PORT
      LAYER met2 ;
        RECT 360.730 439.770 361.010 440.050 ;
    END
  END s_axi_wdata_30
  PIN s_axi_wdata_31
    DIRECTION INPUT ;
    USE SIGNAL ;
    ANTENNAGATEAREA 0.647700 ;
    ANTENNADIFFAREA 0.434700 ;
    PORT
      LAYER met2 ;
        RECT 307.370 439.770 307.650 440.050 ;
    END
  END s_axi_wdata_31
  PIN s_axi_wdata_4
    DIRECTION INPUT ;
    USE SIGNAL ;
    ANTENNAGATEAREA 0.647700 ;
    ANTENNADIFFAREA 0.434700 ;
    PORT
      LAYER met3 ;
        RECT 428.730 368.600 429.330 369.200 ;
    END
  END s_axi_wdata_4
  PIN s_axi_wdata_5
    DIRECTION INPUT ;
    USE SIGNAL ;
    ANTENNAGATEAREA 0.647700 ;
    ANTENNADIFFAREA 0.434700 ;
    PORT
      LAYER met3 ;
        RECT 428.730 402.600 429.330 403.200 ;
    END
  END s_axi_wdata_5
  PIN s_axi_wdata_6
    DIRECTION INPUT ;
    USE SIGNAL ;
    ANTENNAGATEAREA 0.647700 ;
    ANTENNADIFFAREA 0.434700 ;
    PORT
      LAYER met2 ;
        RECT 337.730 439.770 338.010 440.050 ;
    END
  END s_axi_wdata_6
  PIN s_axi_wdata_7
    DIRECTION INPUT ;
    USE SIGNAL ;
    ANTENNAGATEAREA 0.647700 ;
    ANTENNADIFFAREA 0.434700 ;
    PORT
      LAYER met3 ;
        RECT 428.730 389.000 429.330 389.600 ;
    END
  END s_axi_wdata_7
  PIN s_axi_wdata_8
    DIRECTION INPUT ;
    USE SIGNAL ;
    ANTENNAGATEAREA 0.647700 ;
    ANTENNADIFFAREA 0.434700 ;
    PORT
      LAYER met2 ;
        RECT 384.650 439.770 384.930 440.050 ;
    END
  END s_axi_wdata_8
  PIN s_axi_wdata_9
    DIRECTION INPUT ;
    USE SIGNAL ;
    ANTENNAGATEAREA 0.647700 ;
    ANTENNADIFFAREA 0.434700 ;
    PORT
      LAYER met2 ;
        RECT 332.210 439.770 332.490 440.050 ;
    END
  END s_axi_wdata_9
  PIN s_axi_wready
    DIRECTION OUTPUT ;
    USE SIGNAL ;
    ANTENNAGATEAREA 0.434700 ;
    ANTENNADIFFAREA 1.137600 ;
    PORT
      LAYER met2 ;
        RECT 336.810 439.770 337.090 440.050 ;
    END
  END s_axi_wready
  PIN s_axi_wstrb_0
    DIRECTION INPUT ;
    USE SIGNAL ;
    PORT
      LAYER met2 ;
        RECT 34.130 0.000 34.410 0.280 ;
    END
  END s_axi_wstrb_0
  PIN s_axi_wstrb_1
    DIRECTION INPUT ;
    USE SIGNAL ;
    PORT
      LAYER met2 ;
        RECT 35.050 0.000 35.330 0.280 ;
    END
  END s_axi_wstrb_1
  PIN s_axi_wstrb_2
    DIRECTION INPUT ;
    USE SIGNAL ;
    PORT
      LAYER met2 ;
        RECT 35.970 0.000 36.250 0.280 ;
    END
  END s_axi_wstrb_2
  PIN s_axi_wstrb_3
    DIRECTION INPUT ;
    USE SIGNAL ;
    PORT
      LAYER met2 ;
        RECT 36.890 0.000 37.170 0.280 ;
    END
  END s_axi_wstrb_3
  PIN s_axi_wvalid
    DIRECTION INPUT ;
    USE SIGNAL ;
    ANTENNAGATEAREA 0.647700 ;
    ANTENNADIFFAREA 0.434700 ;
    PORT
      LAYER met2 ;
        RECT 335.890 439.770 336.170 440.050 ;
    END
  END s_axi_wvalid
  OBS
      LAYER nwell ;
        RECT 5.330 10.795 423.850 427.230 ;
      LAYER li1 ;
        RECT 5.520 10.795 423.660 427.125 ;
      LAYER met1 ;
        RECT 5.520 10.640 426.350 430.400 ;
      LAYER met2 ;
        RECT 6.530 439.490 56.850 439.770 ;
        RECT 57.690 439.490 57.770 439.770 ;
        RECT 58.610 439.490 58.690 439.770 ;
        RECT 59.530 439.490 95.490 439.770 ;
        RECT 96.330 439.490 101.930 439.770 ;
        RECT 102.770 439.490 102.850 439.770 ;
        RECT 103.690 439.490 106.530 439.770 ;
        RECT 107.370 439.490 107.450 439.770 ;
        RECT 108.290 439.490 111.130 439.770 ;
        RECT 111.970 439.490 112.050 439.770 ;
        RECT 112.890 439.490 115.730 439.770 ;
        RECT 116.570 439.490 118.490 439.770 ;
        RECT 119.330 439.490 119.410 439.770 ;
        RECT 120.250 439.490 120.330 439.770 ;
        RECT 121.170 439.490 122.170 439.770 ;
        RECT 123.010 439.490 127.690 439.770 ;
        RECT 128.530 439.490 128.610 439.770 ;
        RECT 129.450 439.490 130.450 439.770 ;
        RECT 131.290 439.490 131.370 439.770 ;
        RECT 132.210 439.490 135.050 439.770 ;
        RECT 135.890 439.490 136.890 439.770 ;
        RECT 137.730 439.490 139.650 439.770 ;
        RECT 140.490 439.490 140.570 439.770 ;
        RECT 141.410 439.490 142.410 439.770 ;
        RECT 143.250 439.490 147.010 439.770 ;
        RECT 147.850 439.490 147.930 439.770 ;
        RECT 148.770 439.490 154.370 439.770 ;
        RECT 155.210 439.490 155.290 439.770 ;
        RECT 156.130 439.490 156.210 439.770 ;
        RECT 157.050 439.490 157.130 439.770 ;
        RECT 157.970 439.490 162.650 439.770 ;
        RECT 163.490 439.490 165.410 439.770 ;
        RECT 166.250 439.490 167.250 439.770 ;
        RECT 168.090 439.490 168.170 439.770 ;
        RECT 169.010 439.490 170.010 439.770 ;
        RECT 170.850 439.490 170.930 439.770 ;
        RECT 171.770 439.490 171.850 439.770 ;
        RECT 172.690 439.490 174.610 439.770 ;
        RECT 175.450 439.490 175.530 439.770 ;
        RECT 176.370 439.490 176.450 439.770 ;
        RECT 177.290 439.490 177.370 439.770 ;
        RECT 178.210 439.490 178.290 439.770 ;
        RECT 179.130 439.490 179.210 439.770 ;
        RECT 180.050 439.490 180.130 439.770 ;
        RECT 180.970 439.490 181.050 439.770 ;
        RECT 181.890 439.490 182.890 439.770 ;
        RECT 183.730 439.490 183.810 439.770 ;
        RECT 184.650 439.490 186.570 439.770 ;
        RECT 187.410 439.490 188.410 439.770 ;
        RECT 189.250 439.490 190.250 439.770 ;
        RECT 191.090 439.490 191.170 439.770 ;
        RECT 192.010 439.490 192.090 439.770 ;
        RECT 192.930 439.490 193.010 439.770 ;
        RECT 193.850 439.490 193.930 439.770 ;
        RECT 194.770 439.490 194.850 439.770 ;
        RECT 195.690 439.490 195.770 439.770 ;
        RECT 196.610 439.490 196.690 439.770 ;
        RECT 197.530 439.490 197.610 439.770 ;
        RECT 198.450 439.490 198.530 439.770 ;
        RECT 199.370 439.490 199.450 439.770 ;
        RECT 200.290 439.490 201.290 439.770 ;
        RECT 202.130 439.490 202.210 439.770 ;
        RECT 203.050 439.490 210.490 439.770 ;
        RECT 211.330 439.490 211.410 439.770 ;
        RECT 212.250 439.490 212.330 439.770 ;
        RECT 213.170 439.490 213.250 439.770 ;
        RECT 214.090 439.490 214.170 439.770 ;
        RECT 215.010 439.490 215.090 439.770 ;
        RECT 215.930 439.490 216.010 439.770 ;
        RECT 216.850 439.490 216.930 439.770 ;
        RECT 217.770 439.490 220.610 439.770 ;
        RECT 221.450 439.490 221.530 439.770 ;
        RECT 222.370 439.490 225.210 439.770 ;
        RECT 226.050 439.490 228.890 439.770 ;
        RECT 229.730 439.490 230.730 439.770 ;
        RECT 231.570 439.490 232.570 439.770 ;
        RECT 233.410 439.490 234.410 439.770 ;
        RECT 235.250 439.490 236.250 439.770 ;
        RECT 237.090 439.490 237.170 439.770 ;
        RECT 238.010 439.490 238.090 439.770 ;
        RECT 238.930 439.490 239.010 439.770 ;
        RECT 239.850 439.490 239.930 439.770 ;
        RECT 240.770 439.490 240.850 439.770 ;
        RECT 241.690 439.490 241.770 439.770 ;
        RECT 242.610 439.490 244.530 439.770 ;
        RECT 245.370 439.490 251.890 439.770 ;
        RECT 252.730 439.490 254.650 439.770 ;
        RECT 255.490 439.490 255.570 439.770 ;
        RECT 256.410 439.490 256.490 439.770 ;
        RECT 257.330 439.490 260.170 439.770 ;
        RECT 261.010 439.490 261.090 439.770 ;
        RECT 261.930 439.490 262.010 439.770 ;
        RECT 262.850 439.490 262.930 439.770 ;
        RECT 263.770 439.490 264.770 439.770 ;
        RECT 265.610 439.490 271.210 439.770 ;
        RECT 272.050 439.490 272.130 439.770 ;
        RECT 272.970 439.490 274.890 439.770 ;
        RECT 275.730 439.490 278.570 439.770 ;
        RECT 279.410 439.490 279.490 439.770 ;
        RECT 280.330 439.490 280.410 439.770 ;
        RECT 281.250 439.490 281.330 439.770 ;
        RECT 282.170 439.490 286.850 439.770 ;
        RECT 287.690 439.490 288.690 439.770 ;
        RECT 289.530 439.490 305.250 439.770 ;
        RECT 306.090 439.490 306.170 439.770 ;
        RECT 307.010 439.490 307.090 439.770 ;
        RECT 307.930 439.490 308.010 439.770 ;
        RECT 308.850 439.490 308.930 439.770 ;
        RECT 309.770 439.490 309.850 439.770 ;
        RECT 310.690 439.490 310.770 439.770 ;
        RECT 311.610 439.490 311.690 439.770 ;
        RECT 312.530 439.490 312.610 439.770 ;
        RECT 313.450 439.490 319.970 439.770 ;
        RECT 320.810 439.490 327.330 439.770 ;
        RECT 328.170 439.490 328.250 439.770 ;
        RECT 329.090 439.490 329.170 439.770 ;
        RECT 330.010 439.490 331.010 439.770 ;
        RECT 331.850 439.490 331.930 439.770 ;
        RECT 332.770 439.490 332.850 439.770 ;
        RECT 333.690 439.490 333.770 439.770 ;
        RECT 334.610 439.490 335.610 439.770 ;
        RECT 336.450 439.490 336.530 439.770 ;
        RECT 337.370 439.490 337.450 439.770 ;
        RECT 338.290 439.490 338.370 439.770 ;
        RECT 339.210 439.490 339.290 439.770 ;
        RECT 340.130 439.490 354.010 439.770 ;
        RECT 354.850 439.490 354.930 439.770 ;
        RECT 355.770 439.490 357.690 439.770 ;
        RECT 358.530 439.490 360.450 439.770 ;
        RECT 361.290 439.490 369.650 439.770 ;
        RECT 370.490 439.490 382.530 439.770 ;
        RECT 383.370 439.490 384.370 439.770 ;
        RECT 385.210 439.490 426.330 439.770 ;
        RECT 6.530 0.560 426.330 439.490 ;
        RECT 7.090 0.280 7.170 0.560 ;
        RECT 8.010 0.280 8.090 0.560 ;
        RECT 8.930 0.280 9.010 0.560 ;
        RECT 9.850 0.280 9.930 0.560 ;
        RECT 10.770 0.280 10.850 0.560 ;
        RECT 11.690 0.280 11.770 0.560 ;
        RECT 12.610 0.280 12.690 0.560 ;
        RECT 13.530 0.280 13.610 0.560 ;
        RECT 14.450 0.280 14.530 0.560 ;
        RECT 15.370 0.280 15.450 0.560 ;
        RECT 16.290 0.280 16.370 0.560 ;
        RECT 17.210 0.280 17.290 0.560 ;
        RECT 18.130 0.280 18.210 0.560 ;
        RECT 19.050 0.280 19.130 0.560 ;
        RECT 19.970 0.280 20.050 0.560 ;
        RECT 20.890 0.280 20.970 0.560 ;
        RECT 21.810 0.280 21.890 0.560 ;
        RECT 22.730 0.280 22.810 0.560 ;
        RECT 23.650 0.280 23.730 0.560 ;
        RECT 24.570 0.280 24.650 0.560 ;
        RECT 25.490 0.280 25.570 0.560 ;
        RECT 26.410 0.280 26.490 0.560 ;
        RECT 27.330 0.280 27.410 0.560 ;
        RECT 28.250 0.280 28.330 0.560 ;
        RECT 29.170 0.280 29.250 0.560 ;
        RECT 30.090 0.280 30.170 0.560 ;
        RECT 31.010 0.280 31.090 0.560 ;
        RECT 31.930 0.280 32.010 0.560 ;
        RECT 32.850 0.280 32.930 0.560 ;
        RECT 33.770 0.280 33.850 0.560 ;
        RECT 34.690 0.280 34.770 0.560 ;
        RECT 35.610 0.280 35.690 0.560 ;
        RECT 36.530 0.280 36.610 0.560 ;
        RECT 37.450 0.280 129.530 0.560 ;
        RECT 130.370 0.280 151.610 0.560 ;
        RECT 152.450 0.280 163.570 0.560 ;
        RECT 164.410 0.280 169.090 0.560 ;
        RECT 169.930 0.280 170.010 0.560 ;
        RECT 170.850 0.280 172.770 0.560 ;
        RECT 173.610 0.280 173.690 0.560 ;
        RECT 174.530 0.280 178.290 0.560 ;
        RECT 179.130 0.280 180.130 0.560 ;
        RECT 180.970 0.280 181.050 0.560 ;
        RECT 181.890 0.280 185.650 0.560 ;
        RECT 186.490 0.280 191.170 0.560 ;
        RECT 192.010 0.280 193.930 0.560 ;
        RECT 194.770 0.280 219.690 0.560 ;
        RECT 220.530 0.280 220.610 0.560 ;
        RECT 221.450 0.280 221.530 0.560 ;
        RECT 222.370 0.280 225.210 0.560 ;
        RECT 226.050 0.280 239.010 0.560 ;
        RECT 239.850 0.280 241.770 0.560 ;
        RECT 242.610 0.280 248.210 0.560 ;
        RECT 249.050 0.280 260.170 0.560 ;
        RECT 261.010 0.280 261.090 0.560 ;
        RECT 261.930 0.280 262.010 0.560 ;
        RECT 262.850 0.280 262.930 0.560 ;
        RECT 263.770 0.280 264.770 0.560 ;
        RECT 265.610 0.280 278.570 0.560 ;
        RECT 279.410 0.280 281.330 0.560 ;
        RECT 282.170 0.280 283.170 0.560 ;
        RECT 284.010 0.280 304.330 0.560 ;
        RECT 305.170 0.280 308.930 0.560 ;
        RECT 309.770 0.280 309.850 0.560 ;
        RECT 310.690 0.280 325.490 0.560 ;
        RECT 326.330 0.280 369.650 0.560 ;
        RECT 370.490 0.280 370.570 0.560 ;
        RECT 371.410 0.280 372.410 0.560 ;
        RECT 373.250 0.280 376.090 0.560 ;
        RECT 376.930 0.280 398.170 0.560 ;
        RECT 399.010 0.280 426.330 0.560 ;
      LAYER met3 ;
        RECT 0.600 403.600 428.730 427.205 ;
        RECT 0.600 402.200 428.330 403.600 ;
        RECT 0.600 390.000 428.730 402.200 ;
        RECT 0.600 387.240 428.330 390.000 ;
        RECT 0.600 385.920 428.730 387.240 ;
        RECT 0.600 384.520 428.330 385.920 ;
        RECT 0.600 383.200 428.730 384.520 ;
        RECT 0.600 381.800 428.330 383.200 ;
        RECT 0.600 369.600 428.730 381.800 ;
        RECT 0.600 368.200 428.330 369.600 ;
        RECT 0.600 366.880 428.730 368.200 ;
        RECT 0.600 358.680 428.330 366.880 ;
        RECT 0.600 357.360 428.730 358.680 ;
        RECT 0.600 355.960 428.330 357.360 ;
        RECT 0.600 343.760 428.730 355.960 ;
        RECT 0.600 335.600 428.330 343.760 ;
        RECT 1.000 334.200 428.330 335.600 ;
        RECT 0.600 332.840 428.330 334.200 ;
        RECT 0.600 326.080 428.730 332.840 ;
        RECT 0.600 324.680 428.330 326.080 ;
        RECT 0.600 323.360 428.730 324.680 ;
        RECT 1.000 322.000 428.730 323.360 ;
        RECT 1.000 321.960 428.330 322.000 ;
        RECT 0.600 320.600 428.330 321.960 ;
        RECT 0.600 319.280 428.730 320.600 ;
        RECT 0.600 317.920 428.330 319.280 ;
        RECT 1.000 317.880 428.330 317.920 ;
        RECT 1.000 315.200 428.730 317.880 ;
        RECT 1.000 313.800 428.330 315.200 ;
        RECT 0.600 312.480 428.730 313.800 ;
        RECT 0.600 311.120 428.330 312.480 ;
        RECT 1.000 309.720 428.330 311.120 ;
        RECT 1.000 308.400 428.730 309.720 ;
        RECT 1.000 307.000 428.330 308.400 ;
        RECT 1.000 305.640 428.730 307.000 ;
        RECT 0.600 304.320 428.730 305.640 ;
        RECT 1.000 302.920 428.330 304.320 ;
        RECT 0.600 301.560 428.330 302.920 ;
        RECT 0.600 294.800 428.730 301.560 ;
        RECT 0.600 292.040 428.330 294.800 ;
        RECT 0.600 290.720 428.730 292.040 ;
        RECT 0.600 287.960 428.330 290.720 ;
        RECT 0.600 283.920 428.730 287.960 ;
        RECT 0.600 273.000 428.330 283.920 ;
        RECT 0.600 241.760 428.730 273.000 ;
        RECT 1.000 240.360 428.330 241.760 ;
        RECT 0.600 239.000 428.330 240.360 ;
        RECT 0.600 237.680 428.730 239.000 ;
        RECT 0.600 230.840 428.330 237.680 ;
        RECT 0.600 215.920 428.730 230.840 ;
        RECT 1.000 214.520 428.330 215.920 ;
        RECT 0.600 213.160 428.330 214.520 ;
        RECT 0.600 211.840 428.730 213.160 ;
        RECT 0.600 210.440 428.330 211.840 ;
        RECT 0.600 203.680 428.730 210.440 ;
        RECT 1.000 202.280 428.330 203.680 ;
        RECT 0.600 187.360 428.730 202.280 ;
        RECT 0.600 183.240 428.330 187.360 ;
        RECT 0.600 176.480 428.730 183.240 ;
        RECT 0.600 173.720 428.330 176.480 ;
        RECT 0.600 169.680 428.730 173.720 ;
        RECT 0.600 166.920 428.330 169.680 ;
        RECT 0.600 158.800 428.730 166.920 ;
        RECT 0.600 157.400 428.330 158.800 ;
        RECT 0.600 147.920 428.730 157.400 ;
        RECT 0.600 146.520 428.330 147.920 ;
        RECT 0.600 143.840 428.730 146.520 ;
        RECT 0.600 142.440 428.330 143.840 ;
        RECT 0.600 137.040 428.730 142.440 ;
        RECT 0.600 135.640 428.330 137.040 ;
        RECT 0.600 131.600 428.730 135.640 ;
        RECT 0.600 128.840 428.330 131.600 ;
        RECT 0.600 122.080 428.730 128.840 ;
        RECT 0.600 120.680 428.330 122.080 ;
        RECT 0.600 113.920 428.730 120.680 ;
        RECT 0.600 112.520 428.330 113.920 ;
        RECT 0.600 104.400 428.730 112.520 ;
        RECT 0.600 103.000 428.330 104.400 ;
        RECT 0.600 88.080 428.730 103.000 ;
        RECT 0.600 86.680 428.330 88.080 ;
        RECT 0.600 24.160 428.730 86.680 ;
        RECT 0.600 21.400 428.330 24.160 ;
        RECT 0.600 10.715 428.730 21.400 ;
      LAYER met4 ;
        RECT 173.255 47.775 174.240 423.465 ;
        RECT 176.640 47.775 177.540 423.465 ;
        RECT 179.940 47.775 308.825 423.465 ;
  END
END riscv_debug
END LIBRARY

